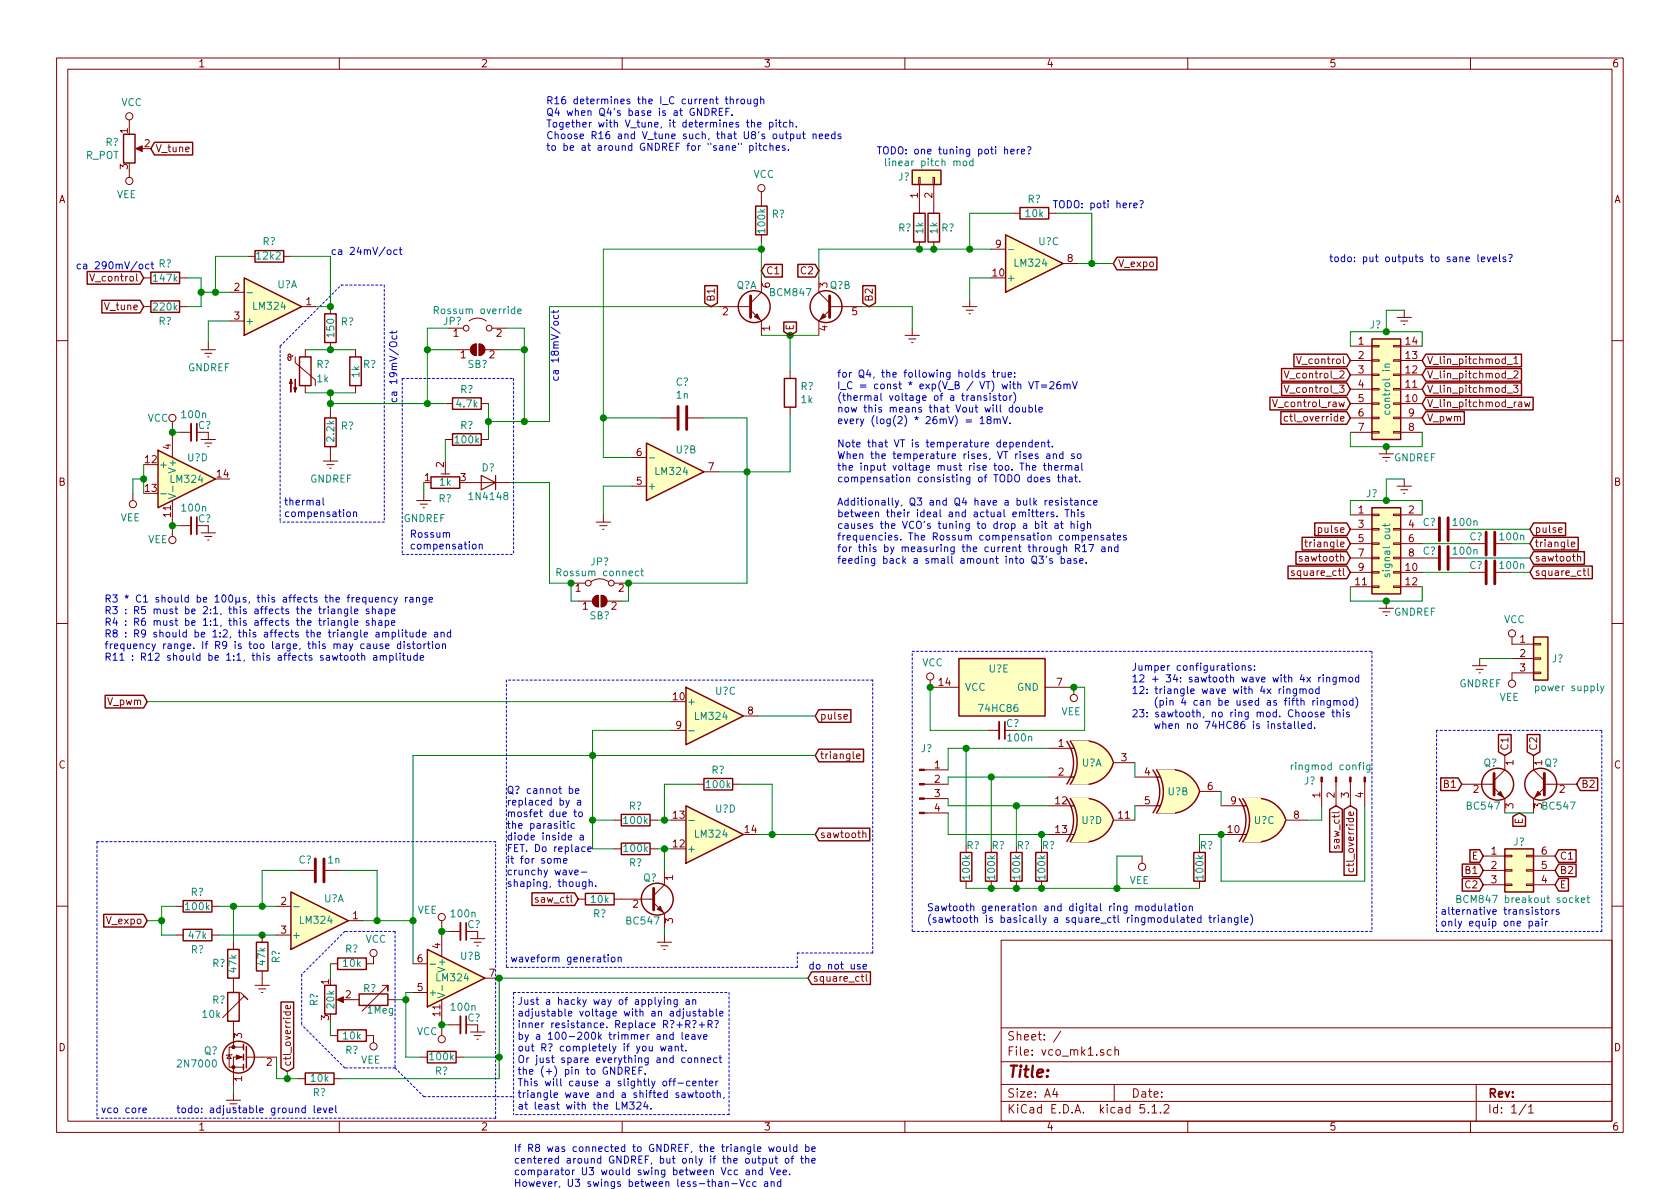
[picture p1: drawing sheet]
<svg xmlns="http://www.w3.org/2000/svg" width="297mm" height="210mm" viewBox="0 0 297 210" stroke-linecap="round" stroke-linejoin="round" font-family="sans-serif">
<defs><g id="words">
<text font-size="2.8" fill="#840000" x="178" y="190.5">Title:</text>
<g font-size="2.1" fill="#840000">
<text x="178" y="184">Sheet: /</text>
<text x="178" y="186.7">File: vco_mk1.sch</text>
<text x="178" y="196.9">KiCad E.D.A. kicad 5.1.2</text>
<text x="178" y="194.1">Size: A4</text>
<text x="200" y="194.1">Date:</text>
<text x="263" y="194.1">Rev:</text>
<text x="263" y="196.9">Id: 1/1</text>
</g>
<g font-size="1.8" fill="#840000">
<text x="35" y="11.9">1</text>
<text x="85" y="11.9">2</text>
<text x="135" y="11.9">3</text>
<text x="185" y="11.9">4</text>
<text x="235" y="11.9">5</text>
<text x="285" y="11.9">6</text>
<text x="22.6" y="23.6" transform="rotate(-90 22.6 23.6)">1</text>
<text x="22.6" y="29.9" transform="rotate(-90 22.6 29.9)">3</text>
<text x="25.6" y="26">2</text>
<text x="27.5" y="26.9">V_tune</text>
<text x="10.4" y="35.9">A</text>
<text x="162.3" y="35" transform="rotate(-90 162.3 35)">1</text>
<text x="164.8" y="35" transform="rotate(-90 164.8 35)">2</text>
<text x="285.4" y="35.9">A</text>
<text x="176" y="43.8">9</text>
<text x="188.7" y="46.3">8</text>
<text x="197.6" y="47.2">V_expo</text>
<text x="16.5" y="49.8">V_control</text>
<text x="41.4" y="51.4">2</text>
<text x="54.1" y="54">1</text>
<text x="126.4" y="53.4" transform="rotate(-90 126.4 53.4)">B1</text>
<text x="135.4" y="48.5">C1</text>
<text x="136.1" y="50.9" transform="rotate(-90 136.1 50.9)">6</text>
<text x="141.7" y="48.5">C2</text>
<text x="146.3" y="50.9" transform="rotate(-90 146.3 50.9)">3</text>
<text x="154.3" y="53.4" transform="rotate(-90 154.3 53.4)">B2</text>
<text x="175.6" y="48.9">10</text>
<text x="18.7" y="54.9">V_tune</text>
<text x="41.4" y="56.5">3</text>
<text x="80.2" y="59.6">1</text>
<text x="87.8" y="59.6">2</text>
<text x="127.8" y="55.7">2</text>
<text x="136.1" y="58.5" transform="rotate(-90 136.1 58.5)">1</text>
<text x="140.3" y="58.5" transform="rotate(-90 140.3 58.5)">E</text>
<text x="146.3" y="58.5" transform="rotate(-90 146.3 58.5)">4</text>
<text x="150.6" y="55.7">5</text>
<text x="81.4" y="63.4">1</text>
<text x="86.5" y="63.4">2</text>
<text x="229.8" y="64.4">V_control</text>
<text x="240.2" y="61">1</text>
<text x="240.2" y="63.5">2</text>
<text x="248.6" y="63.5">13</text>
<text x="248.6" y="61">14</text>
<text x="252.2" y="64.4">V_lin_pitchmod_1</text>
<text x="227.8" y="66.9">V_control_2</text>
<text x="227.8" y="69.5">V_control_3</text>
<text x="240.2" y="66">3</text>
<text x="240.2" y="68.6">4</text>
<text x="240.2" y="71.1">5</text>
<text x="248.6" y="71.1">10</text>
<text x="248.6" y="68.6">11</text>
<text x="248.6" y="66">12</text>
<text x="252.2" y="66.9">V_lin_pitchmod_2</text>
<text x="252.2" y="69.5">V_lin_pitchmod_3</text>
<text x="225.8" y="72">V_control_raw</text>
<text x="227.9" y="74.5">ctl_override</text>
<text x="240.2" y="73.7">6</text>
<text x="240.2" y="76.2">7</text>
<text x="249.1" y="76.2">8</text>
<text x="249.1" y="73.7">9</text>
<text x="252.2" y="72">V_lin_pitchmod_raw</text>
<text x="252.2" y="74.5">V_pwm</text>
<text x="25.7" y="81.9">12</text>
<text x="30.2" y="79.5" transform="rotate(-90 30.2 79.5)">4</text>
<text x="78.5" y="82.6" transform="rotate(-90 78.5 82.6)">2</text>
<text x="112.5" y="80.6">6</text>
<text x="125.2" y="83.2">7</text>
<text x="10.4" y="85.9">B</text>
<text x="25.7" y="87">13</text>
<text x="38.4" y="84.4">14</text>
<text x="75.1" y="85.1">1</text>
<text x="81.4" y="85.1">3</text>
<text x="112.5" y="85.7">5</text>
<text x="285.4" y="85.9">B</text>
<text x="30.2" y="91.4" transform="rotate(-90 30.2 91.4)">11</text>
<text x="233.3" y="94.2">pulse</text>
<text x="240.2" y="90.8">1</text>
<text x="240.2" y="93.3">3</text>
<text x="240.2" y="95.9">5</text>
<text x="249.1" y="90.8">2</text>
<text x="249.1" y="93.3">4</text>
<text x="249.1" y="95.9">6</text>
<text x="271.3" y="94.2">pulse</text>
<text x="229.1" y="101.8">square_ctl</text>
<text x="230.2" y="99.3">sawtooth</text>
<text x="231.6" y="96.8">triangle</text>
<text x="240.2" y="98.4">7</text>
<text x="240.2" y="101">9</text>
<text x="248.6" y="101">10</text>
<text x="249.1" y="98.4">8</text>
<text x="271.3" y="96.8">triangle</text>
<text x="271.3" y="99.3">sawtooth</text>
<text x="271.3" y="101.8">square_ctl</text>
<text x="101.8" y="104.6">1</text>
<text x="103" y="107.8">1</text>
<text x="108.1" y="107.8">2</text>
<text x="109.4" y="104.6">2</text>
<text x="239.7" y="103.5">11</text>
<text x="248.6" y="103.5">12</text>
<text x="268.8" y="113.7">1</text>
<text x="268.8" y="116.2">2</text>
<text x="268.8" y="118.7">3</text>
<text x="19" y="124.7">V_pwm</text>
<text x="119" y="123.8">10</text>
<text x="166" y="121.3">14</text>
<text x="186.8" y="121.3">7</text>
<text x="119.5" y="128.9">9</text>
<text x="132.2" y="126.4">8</text>
<text x="144.9" y="127.2">pulse</text>
<text x="10.4" y="135.9">C</text>
<text x="144.9" y="134.2">triangle</text>
<text x="165.3" y="135.9">1</text>
<text x="187.1" y="132.1">1</text>
<text x="187.1" y="137.2">2</text>
<text x="198.3" y="134.6">3</text>
<text x="202.4" y="137.2">4</text>
<text x="266.7" y="132.8" transform="rotate(-90 266.7 132.8)">C1</text>
<text x="267.6" y="135.4" transform="rotate(-90 267.6 135.4)">1</text>
<text x="271.8" y="132.8" transform="rotate(-90 271.8 132.8)">C2</text>
<text x="272.7" y="135.4" transform="rotate(-90 272.7 135.4)">1</text>
<text x="285.4" y="135.9">C</text>
<text x="165.3" y="138.4">2</text>
<text x="165.3" y="141">3</text>
<text x="165.3" y="143.5">4</text>
<text x="186.7" y="142.2">12</text>
<text x="202.4" y="142.2">5</text>
<text x="213.5" y="139.7">6</text>
<text x="217.6" y="142.2">9</text>
<text x="233.4" y="141.1" transform="rotate(-90 233.4 141.1)">1</text>
<text x="236" y="141.1" transform="rotate(-90 236 141.1)">2</text>
<text x="238.5" y="141.1" transform="rotate(-90 238.5 141.1)">3</text>
<text x="241" y="141.1" transform="rotate(-90 241 141.1)">4</text>
<text x="255.4" y="139.3">B1</text>
<text x="260.5" y="140.2">2</text>
<text x="267.6" y="143" transform="rotate(-90 267.6 143)">3</text>
<text x="272.7" y="143" transform="rotate(-90 272.7 143)">3</text>
<text x="275.7" y="140.2">2</text>
<text x="279.6" y="139.3">B2</text>
<text x="119" y="149.9">12</text>
<text x="119" y="144.8">13</text>
<text x="131.7" y="147.3">14</text>
<text x="144.9" y="148.2">sawtooth</text>
<text x="186.7" y="147.3">13</text>
<text x="197.8" y="144.8">11</text>
<text x="217.1" y="147.3">10</text>
<text x="228.8" y="144.8">8</text>
<text x="236.9" y="149.7" transform="rotate(-90 236.9 149.7)">saw_ctl</text>
<text x="269.2" y="145.7" transform="rotate(-90 269.2 145.7)">E</text>
<text x="119" y="155.7" transform="rotate(-90 119 155.7)">1</text>
<text x="239.4" y="153.3" transform="rotate(-90 239.4 153.3)">ctl_override</text>
<text x="259.2" y="154.6">B1</text>
<text x="260.3" y="152">E</text>
<text x="263.7" y="151.1">1</text>
<text x="263.7" y="153.7">2</text>
<text x="272.6" y="153.7">5</text>
<text x="272.6" y="151.1">6</text>
<text x="275.7" y="152">C1</text>
<text x="275.7" y="154.6">B2</text>
<text x="49.7" y="160">2</text>
<text x="95" y="159.6">saw_ctl</text>
<text x="111.9" y="160.5">2</text>
<text x="259.2" y="157.1">C2</text>
<text x="263.7" y="156.2">3</text>
<text x="272.6" y="156.2">4</text>
<text x="275.7" y="157.1">E</text>
<text x="18.9" y="163.4">V_expo</text>
<text x="49.7" y="165.1">3</text>
<text x="62.4" y="162.6">1</text>
<text x="77.9" y="167.7" transform="rotate(-90 77.9 167.7)">4</text>
<text x="119" y="163.3" transform="rotate(-90 119 163.3)">3</text>
<text x="73.8" y="170.2">6</text>
<text x="86.5" y="172.7">7</text>
<text x="143.7" y="173.6">square_ctl</text>
<text x="58.2" y="174.1" transform="rotate(-90 58.2 174.1)">1</text>
<text x="61.1" y="176.5">2</text>
<text x="73.8" y="175.3">5</text>
<text x="77.9" y="179.6" transform="rotate(-90 77.9 179.6)">11</text>
<text x="10.4" y="185.9">D</text>
<text x="42.8" y="183.6" transform="rotate(-90 42.8 183.6)">3</text>
<text x="58.2" y="180.4" transform="rotate(-90 58.2 180.4)">3</text>
<text x="285.4" y="185.9">D</text>
<text x="42.8" y="191.2" transform="rotate(-90 42.8 191.2)">1</text>
<text x="47.1" y="188.5">2</text>
<text x="51.4" y="188.7" transform="rotate(-90 51.4 188.7)">ctl_override</text>
<text x="35" y="199.9">1</text>
<text x="85" y="199.9">2</text>
<text x="135" y="199.9">3</text>
<text x="185" y="199.9">4</text>
<text x="235" y="199.9">5</text>
<text x="285" y="199.9">6</text>
</g>
<g font-size="1.8" fill="#008484">
<text x="21.4" y="18.8">VCC</text>
<text x="15.2" y="28.1">R_POT</text>
<text x="18.7" y="25.8">R?</text>
<text x="157.5" y="29.4">linear pitch mod</text>
<text x="20.6" y="35">VEE</text>
<text x="133.2" y="31.5">VCC</text>
<text x="158.8" y="31.9">J?</text>
<text x="181.7" y="35.9">R?</text>
<text x="135.3" y="41.1" transform="rotate(-90 135.3 41.1)">100k</text>
<text x="136.5" y="38.5">R?</text>
<text x="158.8" y="40.9">R?</text>
<text x="163.2" y="41.3" transform="rotate(-90 163.2 41.3)">1k</text>
<text x="165.8" y="41.3" transform="rotate(-90 165.8 41.3)">1k</text>
<text x="166.4" y="40.9">R?</text>
<text x="181.4" y="38.4">10k</text>
<text x="28" y="47.3">R?</text>
<text x="45.5" y="45.9">12k2</text>
<text x="46.4" y="43.4">R?</text>
<text x="179.5" y="47.2">LM324</text>
<text x="183.6" y="43.4">U?C</text>
<text x="27.3" y="49.8">147k</text>
<text x="49" y="51">U?A</text>
<text x="130.1" y="51.1">Q?A</text>
<text x="136.3" y="52.4">BCM847</text>
<text x="146.7" y="51.1">Q?B</text>
<text x="177.9" y="49.8">+</text>
<text x="27.3" y="54.9">220k</text>
<text x="28" y="57.4">R?</text>
<text x="43.3" y="57.4">+</text>
<text x="44.9" y="54.8">LM324</text>
<text x="59.1" y="59.5" transform="rotate(-90 59.1 59.5)">150</text>
<text x="60.3" y="57.6">R?</text>
<text x="77.2" y="55.5">Rossum override</text>
<text x="78.4" y="57.4">JP?</text>
<text x="242.2" y="58.1">J?</text>
<text x="33.2" y="65.7">GNDREF</text>
<text x="56" y="65.1">R?</text>
<text x="64.2" y="65.1">R?</text>
<text x="82.7" y="65.1">SB?</text>
<text x="56.1" y="67.6">1k</text>
<text x="63.6" y="66.7" transform="rotate(-90 63.6 66.7)">1k</text>
<text x="81.4" y="69.5">R?</text>
<text x="119.5" y="68.2">C?</text>
<text x="119.6" y="70.5">1n</text>
<text x="141.6" y="69">R?</text>
<text x="141.7" y="71.3">1k</text>
<text x="26.1" y="74.6">VCC</text>
<text x="32.3" y="74">100n</text>
<text x="35" y="75.9">C?</text>
<text x="59.1" y="78" transform="rotate(-90 59.1 78)">2.2k</text>
<text x="60.3" y="76">R?</text>
<text x="80.8" y="72.1">4.7k</text>
<text x="81.4" y="75.9">R?</text>
<text x="245.8" y="72.8" transform="rotate(-90 245.8 72.8)">control in</text>
<text x="28.1" y="82.8">+</text>
<text x="31.1" y="83.2" transform="rotate(-90 31.1 83.2)">V+</text>
<text x="33.1" y="81.6">U?D</text>
<text x="80.6" y="78.4">100k</text>
<text x="85.2" y="83.4">D?</text>
<text x="116" y="84">LM324</text>
<text x="119.5" y="80.2">U?B</text>
<text x="246.5" y="81.6">GNDREF</text>
<text x="30.3" y="85.4">LM324</text>
<text x="54.8" y="85.3">GNDREF</text>
<text x="77.5" y="88.8">R?</text>
<text x="77.8" y="85.9">1k</text>
<text x="83.3" y="88.4">1N4148</text>
<text x="114.4" y="86.6">+</text>
<text x="241.6" y="87.9">J?</text>
<text x="21.3" y="92.2">VEE</text>
<text x="32.3" y="90.5">100n</text>
<text x="35" y="92.4">C?</text>
<text x="71.3" y="92.3">GNDREF</text>
<text x="251.6" y="93">C?</text>
<text x="257.1" y="93">100n</text>
<text x="259.8" y="95.5">C?</text>
<text x="265.3" y="95.5">100n</text>
<text x="26.2" y="96.1">VEE</text>
<text x="98.9" y="101.9">Rossum connect</text>
<text x="104.4" y="100">JP?</text>
<text x="245.8" y="101.5" transform="rotate(-90 245.8 101.5)">signal out</text>
<text x="251.6" y="98.1">C?</text>
<text x="257.1" y="98.1">100n</text>
<text x="259.8" y="100.6">C?</text>
<text x="265.3" y="100.6">100n</text>
<text x="104.3" y="109.5">SB?</text>
<text x="246.5" y="108.9">GNDREF</text>
<text x="265.9" y="110.2">VCC</text>
<text x="163" y="117.8">VCC</text>
<text x="174.8" y="118.9">U?E</text>
<text x="274.4" y="117.1">J?</text>
<text x="121.4" y="124.7">+</text>
<text x="126.5" y="122.9">U?C</text>
<text x="170.6" y="122.2">VCC</text>
<text x="173.3" y="125.9">74HC86</text>
<text x="179.8" y="122.2">GND</text>
<text x="258" y="121.5">GNDREF</text>
<text x="265.1" y="123.9">VEE</text>
<text x="271.8" y="122.2">power supply</text>
<text x="123" y="127.3">LM324</text>
<text x="177.9" y="128.6">C?</text>
<text x="178.3" y="131.1">100n</text>
<text x="187.6" y="126.5">VEE</text>
<text x="125.8" y="136.8">R?</text>
<text x="162.8" y="133">J?</text>
<text x="191.2" y="135.6">U?A</text>
<text x="228.9" y="136.2">ringmod config</text>
<text x="262.3" y="135.6">Q?</text>
<text x="273.1" y="135.6">Q?</text>
<text x="111.2" y="143.2">R?</text>
<text x="125" y="139.4">100k</text>
<text x="126.5" y="143.7">U?D</text>
<text x="206.5" y="140.6">U?B</text>
<text x="230.6" y="138.7">J?</text>
<text x="259.5" y="143.2">BC547</text>
<text x="272.8" y="143.2">BC547</text>
<text x="110.4" y="145.7">100k</text>
<text x="123" y="148.1">LM324</text>
<text x="191.2" y="145.7">U?D</text>
<text x="221.7" y="145.7">U?C</text>
<text x="267.6" y="149.5">J?</text>
<text x="52.8" y="152.7">C?</text>
<text x="58" y="152.7">1n</text>
<text x="110.4" y="150.7">100k</text>
<text x="111.2" y="153.2">R?</text>
<text x="113.7" y="155.9">Q?</text>
<text x="121.4" y="150.7">+</text>
<text x="170.9" y="150.2">R?</text>
<text x="171.5" y="155.4" transform="rotate(-90 171.5 155.4)">100k</text>
<text x="175.3" y="150.2">R?</text>
<text x="175.9" y="155.4" transform="rotate(-90 175.9 155.4)">100k</text>
<text x="179.8" y="150.2">R?</text>
<text x="180.4" y="155.4" transform="rotate(-90 180.4 155.4)">100k</text>
<text x="184.2" y="150.2">R?</text>
<text x="184.8" y="155.4" transform="rotate(-90 184.8 155.4)">100k</text>
<text x="212.2" y="150.2">R?</text>
<text x="212.8" y="155.4" transform="rotate(-90 212.8 155.4)">100k</text>
<text x="32.9" y="161">100k</text>
<text x="33.7" y="158.4">R?</text>
<text x="57.3" y="159.6">U?A</text>
<text x="73.8" y="161.6">VEE</text>
<text x="104.6" y="159.7">10k</text>
<text x="199.7" y="156.3">VEE</text>
<text x="258.7" y="159.7">BCM847 breakout socket</text>
<text x="33.5" y="166">47k</text>
<text x="51.6" y="166">+</text>
<text x="53.1" y="163.4">LM324</text>
<text x="64.6" y="166.7">VCC</text>
<text x="79.9" y="162.2">100n</text>
<text x="82.7" y="164.1">C?</text>
<text x="104.9" y="162.2">R?</text>
<text x="110.9" y="163.5">BC547</text>
<text x="33.8" y="168.6">R?</text>
<text x="37.5" y="171">R?</text>
<text x="41.8" y="171.9" transform="rotate(-90 41.8 171.9)">47k</text>
<text x="46.9" y="170.6" transform="rotate(-90 46.9 170.6)">47k</text>
<text x="49.5" y="170.3" transform="rotate(-90 49.5 170.3)">R?</text>
<text x="60.8" y="171">10k</text>
<text x="61" y="168.4">R?</text>
<text x="77.3" y="173.5">LM324</text>
<text x="78.7" y="171.5" transform="rotate(-90 78.7 171.5)">V+</text>
<text x="81.4" y="169.7">U?B</text>
<text x="37.5" y="177.5">R?</text>
<text x="56.2" y="177.9" transform="rotate(-90 56.2 177.9)">R?</text>
<text x="59.1" y="178.3" transform="rotate(-90 59.1 178.3)">20k</text>
<text x="64.2" y="175.4">R?</text>
<text x="65" y="179.2">1Meg</text>
<text x="75.7" y="176.1">+</text>
<text x="79.9" y="178.7">100n</text>
<text x="35.9" y="180">10k</text>
<text x="60.8" y="183.8">10k</text>
<text x="73.7" y="183.1">VCC</text>
<text x="82.7" y="180.6">C?</text>
<text x="31.7" y="188.8">2N7000</text>
<text x="36.1" y="186.5">Q?</text>
<text x="55" y="191.3">10k</text>
<text x="61.1" y="186.4">R?</text>
<text x="63.8" y="188.1">VEE</text>
<text x="76.1" y="187.5">100k</text>
<text x="76.9" y="190">R?</text>
<text x="55.3" y="193.8">R?</text>
</g>
<g font-size="1.8" fill="#0000c2">
<text x="96.5" y="18.4">R16 determines the I_C current through</text>
<text x="96.5" y="20.5">Q4 when Q4's base is at GNDREF.</text>
<text x="96.5" y="22.5">Together with V_tune, it determines the pitch.</text>
<text x="96.5" y="24.6">Choose R16 and V_tune such, that U8's output needs</text>
<text x="96.5" y="26.7">to be at around GNDREF for &quot;sane&quot; pitches.</text>
<text x="154.9" y="27.3">TODO: one tuning poti here?</text>
<text x="186.1" y="36.8">TODO: poti here?</text>
<text x="13.3" y="47.6">ca 290mV/oct</text>
<text x="58.4" y="45.1">ca 24mV/oct</text>
<text x="234.9" y="46.3">todo: put outputs to sane levels?</text>
<text x="70.2" y="71.4" transform="rotate(-90 70.2 71.4)">ca 19mV/Oct</text>
<text x="98.8" y="67.6" transform="rotate(-90 98.8 67.6)">ca 18mV/oct</text>
<text x="148" y="66.8">for Q4, the following holds true:</text>
<text x="148" y="68.8">I_C = const * exp(V_B / VT) with VT=26mV</text>
<text x="148" y="70.9">(thermal voltage of a transistor)</text>
<text x="148" y="72.9">now this means that Vout will double</text>
<text x="148" y="75">every (log(2) * 26mV) = 18mV.</text>
<text x="148" y="79.1">Note that VT is temperature dependent.</text>
<text x="148" y="81.2">When the temperature rises, VT rises and so</text>
<text x="148" y="83.2">the input voltage must rise too. The thermal</text>
<text x="50.2" y="89.4">thermal</text>
<text x="148" y="85.3">compensation consisting of TODO does that.</text>
<text x="148" y="89.4">Additionally, Q3 and Q4 have a bulk resistance</text>
<text x="50.2" y="91.4">compensation</text>
<text x="72.4" y="95.1">Rossum</text>
<text x="148" y="91.5">between their ideal and actual emitters. This</text>
<text x="148" y="93.5">causes the VCO's tuning to drop a bit at high</text>
<text x="148" y="95.6">frequencies. The Rossum compensation compensates</text>
<text x="72.4" y="97.1">compensation</text>
<text x="148" y="97.6">for this by measuring the current through R17 and</text>
<text x="148" y="99.7">feeding back a small amount into Q3's base.</text>
<text x="18.4" y="106.5">R3 * C1 should be 100µs, this affects the frequency range</text>
<text x="18.4" y="108.6">R3 : R5 must be 2:1, this affects the triangle shape</text>
<text x="18.4" y="110.7">R4 : R6 must be 1:1, this affects the triangle shape</text>
<text x="18.4" y="112.7">R8 : R9 should be 1:2, this affects the triangle amplitude and</text>
<text x="18.4" y="114.8">frequency range. If R9 is too large, this may cause distortion</text>
<text x="18.4" y="116.8">R11 : R12 should be 1:1, this affects sawtooth amplitude</text>
<text x="200" y="118.6">Jumper configurations:</text>
<text x="200" y="120.7">12 + 34: sawtooth wave with 4x ringmod</text>
<text x="200" y="122.7">12: triangle wave with 4x ringmod</text>
<text x="202" y="124.8">(pin 4 can be used as fifth ringmod)</text>
<text x="200" y="126.8">23: sawtooth, no ring mod. Choose this</text>
<text x="202" y="128.9">when no 74HC86 is installed.</text>
<text x="89.5" y="140.4">Q? cannot be</text>
<text x="89.5" y="142.4">replaced by a</text>
<text x="89.5" y="144.5">mosfet due to</text>
<text x="89.5" y="146.6">the parasitic</text>
<text x="89.5" y="148.6">diode inside a</text>
<text x="89.5" y="150.7">FET. Do replace</text>
<text x="89.5" y="152.7">it for some</text>
<text x="89.5" y="154.8">crunchy wave-</text>
<text x="89.5" y="156.8">shaping, though.</text>
<text x="163.8" y="161.1">Sawtooth generation and digital ring modulation</text>
<text x="254.6" y="161.8">alternative transistors</text>
<text x="163.8" y="163.2">(sawtooth is basically a square_ctl ringmodulated triangle)</text>
<text x="254.6" y="163.8">only equip one pair</text>
<text x="90.2" y="170.2">waveform generation</text>
<text x="142.9" y="171.4">do not use</text>
<text x="91.4" y="177.7">Just a hacky way of applying an</text>
<text x="91.4" y="179.8">adjustable voltage with an adjustable</text>
<text x="91.4" y="181.8">inner resistance. Replace R?+R?+R?</text>
<text x="91.4" y="183.9">by a 100-200k trimmer and leave</text>
<text x="91.4" y="185.9">out R? completely if you want.</text>
<text x="91.4" y="188">Or just spare everything and connect</text>
<text x="91.4" y="190">the (+) pin to GNDREF.</text>
<text x="17.8" y="196.8">vco core</text>
<text x="31.1" y="196.8">todo: adjustable ground level</text>
<text x="91.4" y="192.1">This will cause a slightly off-center</text>
<text x="91.4" y="194.2">triangle wave and a shifted sawtooth,</text>
<text x="91.4" y="196.2">at least with the LM324.</text>
<text x="90.8" y="203.7">If R8 was connected to GNDREF, the triangle would be</text>
<text x="90.8" y="205.8">centered around GNDREF, but only if the output of the</text>
<text x="90.8" y="207.8">comparator U3 would swing between Vcc and Vee.</text>
<text x="90.8" y="209.9">However, U3 swings between less-than-Vcc and</text>
</g>
</g></defs>
<g fill="none" stroke="#840000" stroke-width=".18">
<path d="M10 10.3h277v189.9h-277zM12 12.2h273v186.1h-273zM60 10.3v1.9M110 10.3v1.9M160 10.3v1.9M210 10.3v1.9M260 10.3v1.9M22.9 21.2v1.3M22.9 30.1v1.3M24.4 26.3h1M134.6 33.9v2.5M162.4 31.4h.3v1.2h-.3z"/>
<path d="M162.6 32.6v5.1M165 31.4h.2v1.2h-.2zM165.1 32.6v5.1M179.1 37.7h1.2M185.4 37.7h1.3M15.9 48.4l.4 1.3 .4-1.3M25.4 49.1h1.3M25.4 54.2h1.3M31.7 49.1h1.3M31.7 54.2h1.3M40.6 51.7h2.6M40.6 56.8h2.6"/>
<path d="M43.8 45.3h1.3M50.2 45.3h1.2M53.3 54.2h2.6M58.4 54.2v1.3M82.9 56.8a2.53 2.53 0 0 1 3.1 0M87 58h2.5M127 54.2h5.7M132.7 54.9l1.9 1.9v2.5M134.6 41.5v1.3M134.6 49.1v2.6l-1.9 1.9M144.8 49.1v2.6l1.9 1.9M146.7 54.9l-1.9 1.9v2.5"/>
<path d="M146.7 54.2h5.7M160 59.3h2.6M160.7 59.9h1.2M161.3 58v1.3M162.6 42.8v1.3M165.1 42.8v1.3M170.2 54.2h2.5M170.8 54.9h1.3M171.3 55.5h.3M171.4 53v1.2M175.3 44.1h2.5M188 46.6h2.5"/>
<path d="M247 56.1h2.6M247.6 56.8h1.3M248.2 57.4h.2M248.3 54.9v1.2M10 60.2h2M30.5 74.5v1.3M30.5 77.1v3.8M31.7 76.4h2.1M35.6 77.7h2.5M35.6 61.8h2.5M36.2 62.5h1.3M36.2 78.4h1.3"/>
<path d="M36.7 63.1h.3M36.7 79h.3M36.8 60.6v1.2M36.8 76.4v1.3M51.8 62.9l-.2 .2h-.4l-.2-.1v-.3l.3-.1 .1 .2v.8l-.1 .1-.3-.1v-.2l-.2-.2M52.2 63.1v1l3.6 3.1v1M54 61.8v1.3M54 68.2v1.3M58.4 60.6v1.2M58.4 72.6v1.3M58.4 79v2.5M62.9 61.8v1.3"/>
<path d="M62.9 68.2v1.3M78.7 77.7h1.3M78.7 71.4h1.3M80.6 61.8h2.6M83.4 61.2l.4-.3 .4-.1v2.1a1.03 1.03 0 0 1-.9-.6 1.03 1.03 0 0 1 .1-1.1zM84.7 60.8a1.02 1.02 0 0 1 1 1 1.02 1.02 0 0 1-1 1.1zM85.1 77.7h1.3M85.1 71.4h1.3M85.7 61.8h2.6M116.8 73.9h2.8M121.7 73.9h2.8M139.7 65.7v1.2"/>
<path d="M139.7 72v1.3M161.2 60.6h.2M225 70.7l.4 1.2 .5-1.2M227.1 65.6l.4 1.2 .4-1.2M227.1 68.1l.4 1.3 .4-1.3M227.7 73.7l-.4-.1-.2 .3 .1 .5h.5M229.2 63l.5 1.3 .4-1.3M236.7 71.1l.3 .8 .2-.6 .3 .6 .2-.8M237 74l.6-.1v-.2l-.4-.1-.2 .2 .1 .6h.5M238.8 71.4h3.8M238.8 73.9h3.8M238.8 61.2h3.8"/>
<path d="M238.8 68.8h3.8M238.8 66.3h3.8M238.8 63.7h3.8M238.8 76.4h3.8M242.6 76.3h1.2v.3h-1.2zM242.6 73.8h1.2v.2h-1.2zM242.6 71.2h1.2v.3h-1.2zM242.6 68.7h1.2v.3h-1.2zM242.6 66.2h1.2v.2h-1.2zM242.6 63.6h1.2v.3h-1.2zM242.6 61.1h1.2v.2h-1.2zM245.1 79v1.3"/>
<path d="M246.4 76.3h1.2v.3h-1.2zM246.4 73.8h1.2v.2h-1.2zM246.4 71.2h1.2v.3h-1.2zM246.4 68.7h1.2v.3h-1.2zM246.4 66.2h1.2v.2h-1.2zM246.4 63.6h1.2v.3h-1.2zM246.4 61.1h1.2v.2h-1.2zM247.6 71.4h3.9M247.6 73.9h3.9M247.6 61.2h3.9M247.6 68.8h3.9M247.6 66.3h3.9"/>
<path d="M247.6 63.7h3.9M247.6 76.4h3.9M266.5 64.4h.9M266.5 67h.9M266.5 69.5h.9M267.6 68.1h.8l-.4 .5 .3 .1 .1 .5-.3 .2-.5-.1M267.7 63.4l.3-.4v1.3M267.7 65.7l.4-.1 .3 .3-.8 .9h.8M267.7 64.3h.7M268.5 71.1h.5l.1 .8M269.1 71.4h-.5l-.1 .2 .1 .3h.5M269.5 71.1l.3 .8 .2-.6 .3 .6 .2-.8"/>
<path d="M285 60.2h2M23.5 87.2v1.3M30.5 88.5v3.8M30.5 93.6v1.3M31.7 93h2.1M35.6 94.2h2.5M36.2 94.9h1.3M36.7 95.5h.3M36.8 93v1.2M57.1 81.5h2.6M57.8 82.2h1.3M58.3 82.8h.2"/>
<path d="M73.7 88.5h2.5M74.3 89.1h1.3M74.8 89.8h.3M74.9 87.2v1.3M78 83.8h1.5M78.7 82.8v1M82.5 85.3h7.7M105.4 92.3h2.5M106 93h1.3M106.6 93.6h.2M106.7 91.1v1.2M111.8 86h2.5"/>
<path d="M111.8 80.9h2.5M124.5 83.4h2.5M230.7 95.9h.5M230.9 95.4v1.1l.3 .2M238.8 93.6h3.8M238.8 91.1h3.8M238.8 96.1h3.8M238.8 98.7h3.8M242.6 98.5h1.2v.3h-1.2zM242.6 96h1.2v.3h-1.2zM242.6 93.5h1.2v.2h-1.2zM242.6 90.9h1.2v.3h-1.2z"/>
<path d="M243.8 80.3h2.6M244.5 80.9h1.2M245 81.5h.2M246.4 98.5h1.2v.3h-1.2zM246.4 96h1.2v.3h-1.2zM246.4 93.5h1.2v.2h-1.2zM246.4 90.9h1.2v.3h-1.2zM247 86h2.6M247.6 93.6h3.9M247.6 91.1h3.9M247.6 96.1h3.9M247.6 98.7h3.9"/>
<path d="M247.6 86.6h1.3M248.2 87.2h.2M248.3 84.7v1.3M256.3 93.6h2.8M256.3 98.7h2.8M264.5 96.1h2.8M275.6 93.7l.6-.1-.1-.2-.3-.1-.2 .2 .1 .6h.4M277.8 96.3l.6-.1v-.3h-.4l-.2 .1 .1 .6h.5M278.9 98.5l.2-.1h.3l.1 .8M278.9 98v1.2M10 110.3h2M101 103.1h2.5"/>
<path d="M102.2 106.3h2.6M104.5 102.9a2.53 2.53 0 0 1 3.1 0M105 105.6l.4-.3h.4v2a1.03 1.03 0 0 1-.9-.6 1.03 1.03 0 0 1 .1-1.1zM106.3 105.3a1.02 1.02 0 0 1 1 1 1.02 1.02 0 0 1-1 1zM107.3 106.3h2.6M108.6 103.1h2.5M228.8 101l-.3-.1-.2 .2 .1 .2 .4 .1v.3h-.5M238.8 101.2h3.8M238.8 103.8h3.8M242.6 103.6h1.2v.3h-1.2zM242.6 101.1h1.2v.2h-1.2zM243.8 107.6h2.6"/>
<path d="M244.5 108.2h1.2M245 108.8h.2M245.1 106.3v1.3M246.4 103.6h1.2v.3h-1.2zM246.4 101.1h1.2v.2h-1.2zM247.6 101.2h3.9M247.6 103.8h3.9M260.3 117.7h2.6M261 118.4h1.3M261.5 119h.2M261.6 116.5v1.2M264.5 101.2h2.8"/>
<path d="M267.3 112.6v1.3h3.8M267.3 116.5h3.8M271.1 118.9h1.3v.2h-1.3zM271.1 116.3h1.3v.3h-1.3zM271.1 113.8h1.3v.2h-1.3zM271.1 119h-3.8v1.3M279.9 100.9h.5M280.1 100.5v1.1l.3 .2M280.8 100.5v1.1l.2 .2M285 110.3h2M118.7 129.2h2.6M123.2 138.7h1.3"/>
<path d="M129.5 138.7h1.3M131.4 126.6h2.6M149.2 126.7l.6-.1v-.2l-.4-.1-.2 .2 .1 .6h.5M151.5 133.7l.6-.1-.1-.2-.4-.1-.1 .2v.6h.5M163.4 138.7h4.2M163.4 136.1h4.2M164.5 120.3v1.2h5M174.6 129.2h2.1M184.8 121.5h5.1v1.3M185.4 137.4h4.5M185.4 132.3h4.5M196.8 134.9h3.9"/>
<path d="M200.7 137.4h4.4M212.1 139.9h3.8M233.7 138.3v4.2M236.2 138.3v4.2M238.8 138.3v4.2M241.3 138.3v4.2M258.4 138.7h5.8M264.2 139.3l1.9 1.9v2.6M266.1 133.6v2.5l-1.9 1.9M271.1 133.6v2.5l1.9 1.9M273 139.3l-1.9 1.9v2.6M273 138.7h5.8"/>
<path d="M52.7 153.9h2.8M57.5 153.9h2.8M102.2 159h1.3M108.6 150.1h1.3M108.6 145h1.3M108.6 159h7M114.9 150.1h1.3M114.9 145h1.3M115.6 159.6l1.9 1.9v2.6M117.5 153.9v2.6l-1.9 1.9M152.6 147.4l.1-.1h.3l.1 .8M152.6 146.9v1.2"/>
<path d="M163.4 143.8h4.2M163.4 141.2h4.2M170.8 155.8v1.3M175.3 155.8v1.3M179.7 155.8v1.3M184.1 155.8v1.3M185.4 142.5h4.5M185.4 147.6h4.5M196.8 145h3.9M200.7 142.5h4.4M201.9 151.4v1.2M212.1 155.8v1.3"/>
<path d="M215.9 142.5h4.4M215.9 147.6h4.4M227.3 145h3.8M238.5 153.6v.3l.2 .3 .6-.2v-.4M239.3 143.6v.4l-.2 .2-.6-.1v-.5h.3l.1 .6M262.3 153.9h3.8M262.3 151.4h3.8M262.3 156.5h3.8M266.1 156.3h1.2v.3h-1.2zM266.1 153.8h1.2v.2h-1.2zM266.1 151.3h1.2v.2h-1.2zM269.9 156.3h1.2v.3h-1.2z"/>
<path d="M269.9 153.8h1.2v.2h-1.2zM269.9 151.3h1.2v.2h-1.2zM271.1 153.9h3.9M271.1 151.4h3.9M271.1 156.5h3.9M10 160.2h2M31.1 165.3h1.3M31.1 160.3h1.3M37.5 165.3h1.2M37.5 160.3h1.2M41.3 166.6v1.3M41.3 173v2.5"/>
<path d="M42.5 175.5l1.3 1.3-.6-.7-3.8 3.9M45.1 174.2h2.5M45.7 174.9h1.3M46.2 175.5h.3M46.4 165.3v1.3M46.4 171.7v2.5M48.9 165.3h2.5M48.9 160.3h2.5M50.1 178.9h1.3M50.6 178.9l-.1 .4 .2 .2 .6-.1v-.5M51.3 177.8l.1 .4-.2 .2-.6-.1v-.5h.2l.1 .6M58.4 170.4h1.3"/>
<path d="M59.9 176.8h1.1M61.6 162.8h2.5M62.2 176.8h1.3M66 169.2v1.2h-1.2M67.6 174.2h1v1.1v-1.1l-4.6 4.6M68.6 176.8h1.2M73 175.5h2.6M73 170.4h2.6M78.1 162.8v1.3M78.1 165.3v3.9M78.1 176.8v3.8M79.4 164.7h2"/>
<path d="M83.2 166h2.5M83.8 166.6h1.3M84.3 167.3h.3M84.5 164.7v1.3M85.7 173h2.6M116.2 166.6h2.5M116.8 167.3h1.3M117.3 167.9h.3M117.5 165.3v1.3M152.2 172.7h.5M152.4 172.3v1l.3 .2M153.2 172.3v1l.1 .2"/>
<path d="M177 166.3h108v32h-108zM285 160.2h2M40 194.6h2.5M40.5 186.6l.4 .6h-.8zM41 186.4l-.1 .2h-.8l-.1 .1M41.3 185.2h-.8v3.5h2.6M41.3 180.6v4.6M41.3 193.3v1.3M41.3 185.2h1.8M43.1 186.9h-1.8v5.1M43.6 186.9h5.3M52.7 190.7h1.3"/>
<path d="M58.4 183.1h1.3M59.1 190.7h1.2M60 198.3v1.9M64.8 183.1h1.2v1.3M74.3 186.9h1.3M78.1 181.9v1.2M79.4 181.2h2M80.6 186.9h1.3M83.2 182.5h2.5M83.8 183.1h1.3M84.3 183.8h.3M84.5 181.2v1.3"/>
<path d="M110 198.3v1.9M160 198.3v1.9M177 194.8h108M177 191.8h108M177 187.8h108M177 181.8h108M186.5 192.5l-.4 1h1M186.8 193v1M187.6 182.3l-1.3 2M196.5 185.7l-.4-.1-.3 .3v.6l.3 .1 .4-.1M197 191.8v3M197.1 185.7l.2-.1 .4 .1 .1 .9"/>
<path d="M197.1 185.1v1.5M202.3 195.3h-.7l-.1 .7 .3-.1 .5 .1 .1 .2-.1 .5-.2 .1-.6-.1M203 196.7v.1M203.7 195.8l.4-.5v1.5M203.7 196.8h.8M205.2 196.7v.1M205.8 195.5l.2-.2h.4l.3 .5-.9 1h.9M210 198.3v1.9M260 198.3v1.9M261 191.8v6.5M269.8 195.2l-1.2 2M270.3 195.8l.4-.5v1.5"/>
<path d="M270.3 196.8h.8"/>
<circle cx="22.9" cy="32" r=".63"/>
<circle cx="22.9" cy="20.6" r=".63"/>
<circle cx="134.6" cy="33.3" r=".63"/>
<circle cx="82.4" cy="58" r=".51"/>
<circle cx="86.5" cy="58" r=".51"/>
<circle cx="30.5" cy="73.9" r=".63"/>
<circle cx="23.5" cy="89.1" r=".63"/>
<circle cx="30.5" cy="95.5" r=".63"/>
<circle cx="104" cy="103.1" r=".51"/>
<circle cx="108.1" cy="103.1" r=".51"/>
<circle cx="164.5" cy="119.6" r=".63"/>
<circle cx="267.3" cy="112" r=".63"/>
<circle cx="189.9" cy="123.4" r=".63"/>
<circle cx="267.3" cy="120.9" r=".63"/>
<circle cx="201.9" cy="153.3" r=".63"/>
<circle cx="66" cy="168.5" r=".63"/>
<circle cx="78.1" cy="162.2" r=".63"/>
<circle cx="66" cy="185" r=".63"/>
<circle cx="78.1" cy="183.8" r=".63"/>
</g>
<g fill="none" stroke="#008400" stroke-width=".18">
<path d="M179.1 37.7h-7.7v6.4M186.7 37.7h6.3v8.9M33 49.1h2.6v5.1h-2.6M35.6 51.7h5M40.6 56.8h-3.8v3.8M43.8 45.3h-5.7v6.4M51.4 45.3h7v8.9h-2.5M79.4 58h-3.8v13.4M89.5 58h3.2v16.5M127 54.2h-29.8v20.3h-10.8M134.6 44.1h-27.9v36.8h5.1M134.6 59.3h10.2"/>
<path d="M134.6 42.8v6.3M139.7 59.3v6.4M152.4 54.2h8.9v3.8M175.3 49.1h-3.9v3.9M175.3 44.1h-30.5v5M190.5 46.6h6.3M248.3 54.9h-3.2v3.8M30.5 75.8v1.3M30.5 76.4h1.2M54 69.5h8.9M54 61.8h8.9M58.4 69.5v3.1"/>
<path d="M58.4 71.4h20.3M75.6 61.8h5M78.7 77.7v3.8M86.4 71.4v6.3M88.3 61.8h4.4M106.7 73.9h10.1M124.5 73.9h7.6v29.2h-21v3.2h-1.2M139.7 73.3v10.1h-12.7M238.8 61.2v-2.5h12.7v2.5M238.8 76.4v2.6h12.7v-2.6M25.4 84.7h-1.9v2.5M25.4 82.2v5"/>
<path d="M30.5 92.3v1.3M30.5 93h1.2M74.9 85.3v1.9M90.2 85.3h7v17.8h3.8v3.2h1.2M111.8 86h-5.1v5.1M238.8 91.1v-2.6h12.7v2.6M248.3 84.7h-3.2v3.8M251.5 96.1h8.2M259.1 93.6h11.4M259.1 98.7h11.4M267.3 96.1h3.2M238.8 103.8v2.5h12.7v-2.5"/>
<path d="M251.5 101.2h8.2M261.6 116.5h5.7M267.3 101.2h3.2M26 124.1h92.7M118.7 129.2h-13.9v20.9h3.8M123.2 138.7h-5.7v6.3M130.8 138.7h5.7v8.9M134 126.6h10.1M144.1 133.6h-71.1v36.8M164.5 121.5v7.7h10.1M170.8 132.3v17.2M175.3 137.4v12.1"/>
<path d="M185.4 132.3h-17.8v3.8M185.4 137.4h-17.8v1.3M189.9 121.5h1.9v7.7h-12.1M200.7 134.9v2.5M215.9 139.9v2.6M52.7 153.9h-6.3v6.4M60.3 153.9h6.4v8.9M104.8 145h3.8M116.2 145h2.5M116.2 150.1h2.5M117.5 150.1v3.8M134 147.6h10.1"/>
<path d="M167.6 143.8v3.8h17.8M167.6 141.2v1.3h17.8M170.8 157.1h41.3M179.7 142.5v7M184.1 147.6v1.9M200.7 142.5v2.5M201.9 151.4h-4.4v5.7M233.7 142.5v2.5h-2.6M241.3 142.5v13.3h-25.4v-8.2h-3.8v1.9M266.1 143.8h5M26 162.8h2.6M31.1 160.3h-2.5v5h2.5"/>
<path d="M38.7 160.3h10.2M38.7 165.3h10.2M41.3 160.3v6.3M58.4 170.4v2.6M64.1 162.8h8.9M69.8 176.8h2M73 175.5h-1.2v11.4h2.5M78.1 164.1v1.2M78.1 164.7h1.3M117.5 164.1v1.2M142.9 173h-54.6v17.7h-28M41.3 192v1.3"/>
<path d="M48.9 186.9v3.8h3.8M50.8 189.5v1.2M58.4 180.6v2.5M78.1 180.6v1.3M78.1 181.2h1.3M81.9 186.9h6.4"/>
</g>
<g fill="#008400" stroke="#008400" stroke-width=".25">
<circle cx="46.4" cy="160.3" r=".51"/>
<circle cx="28.6" cy="162.8" r=".51"/>
<circle cx="41.3" cy="160.3" r=".51"/>
<circle cx="46.4" cy="165.3" r=".51"/>
<circle cx="88.3" cy="186.9" r=".51"/>
<circle cx="66.7" cy="162.8" r=".51"/>
<circle cx="117.5" cy="145" r=".51"/>
<circle cx="104.8" cy="133.6" r=".51"/>
<circle cx="73" cy="162.8" r=".51"/>
<circle cx="104.8" cy="145" r=".51"/>
<circle cx="86.4" cy="74.5" r=".51"/>
<circle cx="58.4" cy="71.4" r=".51"/>
<circle cx="58.4" cy="69.5" r=".51"/>
<circle cx="58.4" cy="61.8" r=".51"/>
<circle cx="171.5" cy="44.1" r=".51"/>
<circle cx="193" cy="46.6" r=".51"/>
<circle cx="106.7" cy="73.9" r=".51"/>
<circle cx="132.1" cy="83.4" r=".51"/>
<circle cx="38.1" cy="51.7" r=".51"/>
<circle cx="35.6" cy="51.7" r=".51"/>
<circle cx="58.4" cy="54.2" r=".51"/>
<circle cx="88.3" cy="173" r=".51"/>
<circle cx="136.5" cy="147.6" r=".51"/>
<circle cx="215.9" cy="147.6" r=".51"/>
<circle cx="184.2" cy="157.1" r=".51"/>
<circle cx="179.7" cy="157.1" r=".51"/>
<circle cx="175.3" cy="157.1" r=".51"/>
<circle cx="184.2" cy="147.6" r=".51"/>
<circle cx="179.7" cy="142.5" r=".51"/>
<circle cx="175.3" cy="137.4" r=".51"/>
<circle cx="170.8" cy="132.3" r=".51"/>
<circle cx="197.5" cy="157.1" r=".51"/>
<circle cx="245.1" cy="106.3" r=".51"/>
<circle cx="245.1" cy="88.5" r=".51"/>
<circle cx="139.7" cy="59.3" r=".51"/>
<circle cx="134.6" cy="44.1" r=".51"/>
<circle cx="25.4" cy="84.7" r=".51"/>
<circle cx="75.6" cy="71.4" r=".51"/>
<circle cx="92.7" cy="74.5" r=".51"/>
<circle cx="101" cy="103.1" r=".51"/>
<circle cx="111.1" cy="103.1" r=".51"/>
<circle cx="75.6" cy="61.8" r=".51"/>
<circle cx="92.7" cy="61.8" r=".51"/>
<circle cx="165.1" cy="44.1" r=".51"/>
<circle cx="162.6" cy="44.1" r=".51"/>
<circle cx="245.1" cy="58.7" r=".51"/>
<circle cx="245.1" cy="79" r=".51"/>
<circle cx="78.1" cy="181.2" r=".51"/>
<circle cx="78.1" cy="164.7" r=".51"/>
<circle cx="30.5" cy="93" r=".51"/>
<circle cx="30.5" cy="76.4" r=".51"/>
<circle cx="164.5" cy="121.5" r=".51"/>
<circle cx="189.9" cy="121.5" r=".51"/>
<circle cx="117.5" cy="150.1" r=".51"/>
<circle cx="50.8" cy="190.7" r=".51"/>
<circle cx="71.8" cy="176.8" r=".51"/>
</g>
<g fill="none" stroke="#840000" stroke-width=".25">
<path d="M21.8 23.7h2.1v5.1h-2.1zM27.3 25.2h6.8v2.2h-6.8l-.6-1.1zM133.6 36.4h2v5.1h-2zM161.3 30.1h5.1v2.5h-5.1zM161.5 37.7h2.1v5.1h-2.1zM164.1 37.7h2v5.1h-2zM180.3 36.7h5.1v2h-5.1zM15.4 48h9.4l.6 1.1-.6 1.2h-9.4zM18 53.1h6.8l.6 1.1-.6 1.1h-6.8zM26.7 48.1h5v2.1h-5zM26.7 53.2h5v2h-5zM43.2 49.1l10.1 5.1-10.1 5.1z"/>
<path d="M45.1 44.3h5.1v2h-5.1zM57.4 55.5h2v5.1h-2zM124.6 50.5h2.2v3.1l-1.1 .6-1.1-.6zM135.3 46.8h3v2.2h-3l-.7-1.1zM138.6 56.9h2.2v1.8l-1.1 .6-1.1-.6zM141.1 46.8h3l.7 1.1-.7 1.1h-3zM152.6 50.5h2.2v3.1l-1.1 .6-1.1-.6zM177.8 41.5l10.2 5.1-10.2 5.1zM197.5 45.5h7v2.2h-7l-.7-1.1zM242.6 59.9h5v17.8h-5zM27.9 79.6l10.2 5.1-10.2 5.1zM53 63.1h2v5.1h-2z"/>
<path d="M57.4 73.9h2v5.1h-2zM61.8 63.1h2.1v5.1h-2.1zM80 76.7h5.1v2h-5.1zM80 70.4h5.1v2h-5.1zM114.3 78.4l10.2 5-10.2 5.1zM138.7 66.9h2v5.1h-2zM224.5 70.3h13.6l.7 1.1-.7 1.1h-13.6zM226.5 72.8h11.6l.7 1.1-.7 1.1h-11.6zM226.6 65.2h11.5l.7 1.1-.7 1.1h-11.5zM226.6 67.7h11.5l.7 1.1-.7 1.1h-11.5zM228.8 62.6h9.3l.7 1.1-.7 1.2h-9.3zM252.1 62.6h16.9v2.3h-16.9l-.6-1.2z"/>
<path d="M252.1 65.2h16.9v2.2h-16.9l-.6-1.1zM252.1 67.7h16.9v2.2h-16.9l-.6-1.1zM252.1 70.3h19v2.2h-19l-.6-1.1zM252.1 72.8h6.8v2.2h-6.8l-.6-1.1zM76.2 84.3h5.1v2.1h-5.1zM229.1 97.6h9l.7 1.1-.7 1.1h-9zM230.2 95h7.9l.7 1.1-.7 1.2h-7.9zM232.5 92.5h5.6l.7 1.1-.7 1.1h-5.6zM242.6 89.8h5v15.2h-5zM271.1 92.5h5.7v2.2h-5.7l-.6-1.1zM271.1 95h7.9v2.3h-7.9l-.6-1.2zM271.1 97.6h9v2.2h-9l-.6-1.1z"/>
<path d="M169.5 116.5h15.3v10.1h-15.3zM227.7 100.1h10.4l.7 1.1-.7 1.1h-10.4zM271.1 112.6h2.6v7.7h-2.6zM271.1 100.1h10.4v2.2h-10.4l-.6-1.1zM18.6 123h6.8l.6 1.1-.6 1.1h-6.8zM121.3 121.5l10.1 5.1-10.1 5.1zM124.5 137.7h5v2h-5zM144.8 132.5h7.9v2.2h-7.9l-.7-1.1zM144.8 125.5h5.6v2.2h-5.6l-.7-1.1zM188.6 131.1a6.6 6.6 0 0 1 0 7.6M189.2 138.7h3.2M189.2 131.1h3.2"/>
<path d="M189.3 131.1a6.6 6.6 0 0 1 0 7.6M192.4 131a5.2 5.2 0 0 1 4.4 3.8M196.8 134.9a5.2 5.2 0 0 1-4.4 3.8M203.9 136.2a6.6 6.6 0 0 1 0 7.5M207.6 136.1a5.2 5.2 0 0 1 4.5 3.8M207.6 136.1l-3.1 .1a6.6 6.6 0 0 1 0 7.5l3.1 .1M212.1 140a5.2 5.2 0 0 1-4.5 3.8M254.7 137.6h3.1l.6 1.1-.6 1.1h-3.1zM264.9 129.9h2.3v3.1l-1.1 .6-1.2-.6zM270 129.9h2.3v3.1l-1.2 .6-1.1-.6zM279.4 137.6h3.1v2.2h-3.1l-.6-1.1zM32.4 159.3h5.1v2h-5.1z"/>
<path d="M51.4 157.7l10.2 5.1-10.2 5.1zM94.1 157.9h7.5l.6 1.1-.6 1.1h-7.5zM103.5 158h5.1v2h-5.1zM109.9 149.1h5v2h-5zM109.9 144h5v2h-5zM121.3 142.5l10.1 5.1-10.1 5zM144.8 146.5h9v2.2h-9l-.7-1.1zM169.8 150.7h2v5.1h-2zM174.2 150.7h2.1v5.1h-2.1zM178.7 150.7h2v5.1h-2zM183.1 150.7h2.1v5.1h-2.1zM188.6 141.2a6.6 6.6 0 0 1 0 7.6"/>
<path d="M189.2 148.8h3.2M189.2 141.2h3.2M189.3 141.2a6.6 6.6 0 0 1 0 7.6M192.4 141.2a5.2 5.2 0 0 1 4.4 3.8M196.8 145.1a5.2 5.2 0 0 1-4.4 3.8M211.1 150.7h2v5.1h-2zM219.1 141.2a6.6 6.6 0 0 1 0 7.6M222.9 141.2a5.2 5.2 0 0 1 4.4 3.8M222.9 141.2h-3.2a6.6 6.6 0 0 1 0 7.6h3.2M227.3 145.1a5.2 5.2 0 0 1-4.4 3.8M235.1 143.1l1.1-.6 1.1 .6v7.6h-2.2zM237.6 143.1l1.2-.6 1.1 .6v11.7h-2.3z"/>
<path d="M258.5 152.8h3.1l.7 1.1-.7 1.1h-3.1zM258.5 155.3h3.1l.7 1.2-.7 1.1h-3.1zM259.9 150.3h1.7l.7 1.1-.7 1.1h-1.7zM266.1 150.1h5v7.6h-5zM267.5 144.4l1.1-.6 1.1 .6v1.7h-2.2zM275.6 155.3h1.7v2.3h-1.7l-.6-1.1zM275.6 150.3h3.1v2.2h-3.1l-.6-1.1zM275.6 152.8h3.1v2.2h-3.1l-.6-1.1zM18.3 161.7h7.1l.6 1.1-.6 1.1h-7.1zM32.4 164.3h5.1v2.1h-5.1zM40.3 167.9h2v5.1h-2zM40.3 175.5h2v5.1h-2z"/>
<path d="M45.3 166.6h2.1v5.1h-2.1zM49.7 177.2h2.2v11.6l-1.1 .7-1.1-.7zM57.4 174.2h2v5.1h-2zM59.7 169.4h5.1v2h-5.1zM63.5 175.8h5.1v2h-5.1zM75.6 167.9l10.1 5.1-10.1 5zM143.5 171.9h10.4v2.2h-10.4l-.6-1.1zM43.1 184.7v1M43.1 186.4v1M43.1 188.2v1M43.6 185v3.8M54 189.7h5.1v2.1h-5.1z"/>
<path d="M59.7 182.1h5.1v2h-5.1zM75.6 185.9h5v2.1h-5z"/>
<circle cx="133.3" cy="54.2" r="2.82"/>
<circle cx="146" cy="54.2" r="2.82"/>
<circle cx="264.8" cy="138.7" r="2.82"/>
<circle cx="272.4" cy="138.7" r="2.82"/>
<circle cx="116.2" cy="159" r="2.82"/>
<circle cx="42.2" cy="186.9" r="2.82"/>
</g>
<g fill="none" stroke="#0000c2" stroke-width=".18">
<path d="M124.6 19.1a.64 .64 0 0 1 .8 .7 .64 .64 0 0 1-.8 .6zM125.9 19.8h.6l.1-.2v-.3l-.2-.2h-.5v1.3M126.2 19.8l.4 .6M127.2 19.8h.4M127.8 19.1h-.6v1.3h.6M128.2 17.5h.5M128.3 19.8h.5M128.4 17.1v1.1l.3 .2M128.9 19.1h-.6v1.3M129.1 17.6l.2-.1 .3 .1 .1 .8M129.1 17.1v1.3M130.3 17.5v.9"/>
<path d="M130.6 17.5l-.2 .1-.1 .1M131.1 17.6l.3-.1 .2 .1-.1 .7-.3 .1-.2-.3zM132.2 17.5l.1 .8 .3 .1 .1-.2M132.7 17.5v.9M133.9 17.5v1l-.2 .3-.4-.1M133.9 17.6l-.4-.1-.2 .2 .1 .6h.5M134.5 17.6l.2-.1 .3 .1 .1 .8M134.5 17.1v1.3M129.4 20.3v.1M132.6 25.8l.3-.1 .3 .3-.2 .5h-.4M132.6 25.7v1.3M132.9 21.8l.1-.2 .3 .1 .1 .8"/>
<path d="M132.9 21.2v1.3M133.7 25.7v.9M134 22l.6-.1-.1-.2-.4-.1-.1 .2v.6h.5M134.1 25.7h.5M134.3 25.3v1.1l.3 .2M135.6 25.8l-.4-.1-.2 .3 .1 .5h.5M136.1 21.7l.3-.1 .3 .3-.1 .5h-.5M136.1 21.6v1.3M136.1 25.9l.2-.2 .3 .1 .1 .8M136.1 25.3v1.3M137.2 21.2v.1M137.2 26.2l.6-.1v-.3l-.4-.1-.2 .2 .1 .6h.5"/>
<path d="M137.2 21.6v.9M137.6 21.6h.5M137.8 21.2v1.1l.3 .2M138.8 25.8l-.3-.1-.2 .2 .1 .2 .4 .1v.3h-.5M138.9 23.7h.4M139 23.3v1.1l.3 .1M139.1 21.7l-.4-.1-.2 .3 .1 .5h.5M139.4 26.5v.1M139.6 21.8l.2-.2 .3 .1 .1 .8M139.6 21.2v1.3M139.8 23.7h.3l.3 .2-.1 .6h-.5M139.8 23.7v1.3"/>
<path d="M140.8 22.3v.2M140.9 23.7l.1 .8h.3l.2-.1M141.5 23.7v.8M141.9 23.7h.5M142.1 23.3v1.1l.3 .1M143.8 23.8l.1-.1h.3l.1 .8M143.8 23.7v.8M144.9 24.1l.5-.1v-.3h-.4l-.1 .2v.6h.5M145.9 24.1l.6-.1v-.3h-.4l-.2 .2 .1 .6h.5M147.6 23.7h-.3l-.3 .2 .1 .6h.5M147.6 23.3v1.2M148.7 23.7h-.3l-.2 .2v.1l.5 .2v.3h-.5"/>
<path d="M178.7 26.8l.6-.1-.1-.3h-.3l-.2 .2 .1 .6h.4M179.9 26.4v.8M180.2 26.4l-.3 .2M180.6 26.8l.6-.1-.1-.3h-.3l-.2 .2v.6h.5M181.7 26h.4l.2 .1-.4 .6M181.9 27.1v.1M200.5 36.3l.6-.1-.1-.2-.4-.1-.1 .2v.6h.5M201.5 35.6l.5-.1 .1 .2-.3 .6M201.8 36.6v.1M24.6 46.8l.2-.1 .4 .1v.5l-.1 .2h-.3l-.2-.1zM26.3 46.8l-.3-.1-.3 .2 .2 .6h.4M26.7 46.7h.5"/>
<path d="M26.9 46.3v1.1l.3 .1M68.6 44.2h.3l.2 .2-.1 .6h-.3l-.2-.2zM69.3 58.5v.5M69.4 59.4l-.1 .3 .2 .3 .6-.1v-.5M70.2 58.5l-.2 .3h-1.1M70.2 44.2h-.4l-.2 .2 .1 .6h.5M70.6 44.2h.5M70.8 43.7v1.1l.3 .2M97.9 54.9v.5M97.9 56.9l.6-.1 .2 .3v.3l-.6 .1-.2-.3zM97.9 55.7v.4l.2 .2 .6-.1v-.5M98.7 54.9l-.1 .3h-1.1"/>
<path d="M261.3 45v1.1l.2 .2M261.9 45.8l.6-.1v-.2l-.4-.1-.2 .2 .1 .6h.5M263 45.4l.2 .9 .4-.9M264 45.8l.6-.1-.1-.2-.3-.1-.2 .2v.6h.5M265.1 45v1.1l.2 .2M266.2 45.5l-.3-.1-.2 .2 .1 .2 .4 .1v.3h-.5M266.8 45.1l.4-.1 .2 .2-.4 .6M267 46.1v.2M69 60.6a.8 .8 0 0 1 1.2 .2l-.1 .3a.7 .7 0 0 1-.7 .2 .7 .7 0 0 1-.5-.5zM172.9 70.1l.2-.1h.3v.8M173.1 65.9h-.4l-.3 .2 .2 .5h.5M173.1 65.4v1.3"/>
<path d="M173.3 74l.4-.3v1.2M173.3 74.9h.7M174.1 65.9h-.3l-.2 .1 .1 .2 .4 .1v.3h-.5M174.4 70h-.3l-.1 .1v.2l.4 .2v.3h-.4M174.8 74.2l-.3-.2 .1-.2 .2-.1 .4 .1v.3l-.6 .2-.1 .1v.3l.3 .2h.3l.1-.2v-.4l-.2-.1M175.1 70v.8M175.5 65.9h.4M175.7 65.4v1.1l.2 .2M175.8 74.2l.2-.1h.3v.8M175.8 74.1v.8M176.1 70h-.3l-.2 .1 .1 .2 .4 .2v.3h-.5M176.3 74.3l.2-.2h.3l.1 .8"/>
<path d="M176.4 65.9v.8M176.5 70h.5M176.7 69.5v1.1l.3 .2M176.7 65.9l-.3 .2M177.2 65.9v.7l.3 .1 .2-.1M177.3 73.7l.4 1.2 .4-1.2M177.5 70h.3l.2 .1-.1 .7h-.3l-.3-.2zM177.7 65.9v.8M178.3 66.3l.6-.1-.1-.3h-.4l-.1 .1v.6h.5M178.6 74.8v.1M178.6 70v.8M178.9 70l-.3 .2"/>
<path d="M179 72.1l-.3-.1-.3 .3 .2 .5h.4M179 71.6v1.3M179.2 69.4a1.47 1.47 0 0 1 0 1.9M179.4 66.6v.1M179.4 65.9v.1M179.7 78.6l.6-.1-.1-.2-.4-.1-.1 .2v.6h.5M179.7 72.1l.3-.1 .3 .3-.2 .5-.3 .1-.2-.3zM180.8 72v.8l.4 .1 .1-.2M180.8 78.3l.2-.1 .3 .1v.7M180.8 78.2v.8M181.3 72v.9M181.9 67.5l.4 1.3 .4-1.3"/>
<path d="M181.9 72.1l.4-.1 .2 .3-.1 .5h-.5M181.9 71.6v1.3M182.5 78.3l-.4-.1-.2 .2 .1 .6h.5M182.5 77.8v1.2M183 67.5h.7M183 78.6l.6-.1v-.2l-.4-.1-.2 .2 .1 .6h.5M183.1 71.6v1.1l.2 .2M183.3 67.5v1.3M183.7 72.4l.6-.1v-.2l-.4-.1-.2 .2 .1 .6h.5M184.1 68.1h1M184.1 68.4h1M184.2 78.3l.2-.1 .3 .1v.7"/>
<path d="M184.2 78.2v.8M185.1 78.2h.5M185.3 77.8v1.1l.3 .1M185.6 67.6l.5-.1 .3 .3-.1 .2-.7 .8h.8M186.1 78.9v.1M187.5 67.5l-.5 .1-.2 .4 .1 .6 .2 .2 .4-.1 .1-.2-.1-.5h-.4l-.3 .2M187.9 79.8v1.3M188.1 68l.2-.1 .3 .1 .1 .8M188.1 67.9v.9M188.7 68.1l.1-.2 .4 .1v.8M189.6 67.5l.4 1.3 .5-1.3M57.1 88v1.1l.2 .2"/>
<path d="M61.4 90.6l.3-.1 .2 .1-.1 .7-.3 .1-.2-.3zM62.5 90.6l.2-.1 .3 .1v.8M62.5 90.5v.9M78.9 94.4l.2-.2h.3l.1 .8M83.6 96.3l.3-.1 .2 .2v.6l-.3 .1-.3-.3zM84.7 96.4l.2-.2 .3 .1 .1 .8M84.7 96.2v.9M182.5 98.5l.2-.2a.47 .47 0 0 1 .6 .5l-.1 .6-.2 .2h-.4a1 1 0 0 1-.1-1.1zM182.5 82.7l.7-.1-.1-.2-.4-.1-.2 .2 .1 .6h.5M182.7 99.3l.6 .4M183.1 92.7l.4-.1 .2 .2-.1 .6h-.5M183.1 90.5h.5"/>
<path d="M183.3 90.1v1.1l.3 .2M183.7 98.3h.8l-.4 .5 .3 .2v.5l-.1 .1-.6-.1M183.9 91l.7-.1-.1-.3-.4-.1-.2 .2 .1 .6h.5M184 84.8l.6-.1v-.3h-.4l-.2 .2 .1 .6h.5M184.3 92.2v.1M184.3 92.6v.8M184.5 82.3h.5M184.7 81.9v1.1l.3 .2M184.7 92.6h.4M184.8 92.2v1.1l.3 .1M185.1 80.3h.5v.8M185.1 90.5v.9"/>
<path d="M185.4 82.4l.2-.1 .3 .1v.8M185.4 81.9v1.3M185.4 90.5l-.3 .3M185.5 88.9l.6-.1v-.3h-.4l-.2 .2 .1 .6h.5M185.6 84.4h-.3l-.2 .2v.1l.5 .2v.3h-.5M185.6 80.6h-.4l-.2 .2 .1 .2h.5M186.1 98.8h-.3l-.2 .2v.1l.5 .2v.3h-.5M186.2 80.4l.2-.1h.3l.1 .8M186.2 80.3v.8M186.3 90.6l-.3-.1-.2 .2 .1 .2 .4 .1v.3h-.5M186.5 82.7l.6-.1-.1-.2-.3-.1-.2 .2v.6h.5M186.5 92.7h.5l.1 .7"/>
<path d="M186.9 91.3v.1M187 84.4h.5M187.1 88.5h-.3l-.2 .2 .1 .1 .4 .2v.3h-.5M187.1 92.9l-.4 .1-.2 .1v.3h.6M187.1 83.9v1.1l.4 .2M187.5 92.6h.5M187.6 98.8h.4l.2 .2-.1 .6h-.5M187.6 82.3v.9M187.6 98.3v1.3M187.7 88.1v.1M187.7 92.2v1.1l.3 .1M187.7 88.5v.8"/>
<path d="M187.9 84.5l.2-.1h.3v.8M187.9 83.9v1.3M187.9 80.3h-.3l-.3 .2 .2 .5h.4M188 82.3l-.4 .2M188.1 96.8l.1-.1 .3 .1 .1 .8M188.1 96.3v1.3M188.3 90.1h.7M188.4 82.4l.2-.1 .3 .1 .1 .8M188.4 82.3v.9M188.7 90.1v1.3M188.7 88.5h-.3l-.2 .2 .1 .1 .4 .2v.3h-.5M188.8 98.8h.5v.8"/>
<path d="M189 82.5l.2-.2 .2 .1 .1 .8M189 84.4h.5l.1 .8M189.2 88.5h.4M189.3 88.1v1l.3 .2M189.3 99.1h-.4l-.2 .2 .1 .3h.5M189.4 92.7l.2-.1 .3 .1v.7M189.4 92.2v1.2M189.4 90.7l.2-.2 .3 .1 .1 .8M189.4 90.1v1.3M189.6 84.7h-.4l-.2 .2v.3h.6M189.9 80.3h-.3l-.2 .1 .1 .2 .4 .1v.3h-.5M190 84.4h.5"/>
<path d="M190 88.5h.5l.1 .8M190.1 82.4h.5l.1 .8M190.2 83.9v1.1l.3 .2M190.2 96.9h.6l.1-.2-.1-.3-.1-.1h-.5v1.3M190.3 98.8h-.3l-.1 .2v.1l.4 .2v.3h-.4M190.5 96.9l.4 .7M190.5 80.4l.2-.1 .4 .1v.5l-.1 .1-.3 .1-.2-.1zM190.5 92.2v.1M190.5 92.6v.8M190.6 88.8h-.4l-.2 .2v.3h.6M190.6 90.1v.1M190.6 90.5v.9"/>
<path d="M190.7 82.6l-.5 .1-.2 .1 .2 .4 .5-.1M190.9 85.1v.1M190.9 99.2l.6-.1-.1-.3h-.3l-.2 .2 .1 .6h.4M191.2 88.6l.2-.1h.3v.8M191.2 88.5v.8M191.3 81.9v1.1l.1 .2M191.3 94.7h.4l.2 .2-.1 .5h-.5M191.3 94.7v1.2M191.4 96.6l.3-.3v1.3M191.4 97.6h.7M191.6 90.6l-.3-.1-.2 .2 .1 .2 .4 .1v.3h-.5M191.7 92.6v1l-.3 .3-.3-.1"/>
<path d="M191.7 92.7l-.4-.1-.2 .2 .1 .6h.5M192 99.5v.1M192.3 92.7l.2-.1 .3 .1v.7M192.3 92.2v1.2M192.4 95.1l.6-.1v-.3h-.4l-.2 .1 .1 .6h.5M192.5 96.3h.9l-.6 1.3M192.9 88.5h-.4l-.2 .2 .1 .6h.5M193.4 88.9l.6-.1-.1-.3h-.4l-.1 .2v.6h.5M193.5 94.8l.3-.1h.2l.1 .8M193.5 94.7v.8M194.8 96.8h.5l.1 .8M195.1 94.7h-.3l-.2 .1 .1 .2 .4 .1v.3h-.5"/>
<path d="M195.4 97l-.5 .1-.1 .2v.2h.6M195.7 94.7h.5l.1 .8M196 96.8l.2-.1 .3 .1v.8M196 96.7v.9M196.3 95h-.4l-.2 .2v.2h.6M196.7 94.7h.5M196.9 94.2v1.1l.3 .2M197.6 95.1l.5-.1v-.3h-.4l-.1 .1v.6h.5M197.7 96.8l-.4-.1-.2 .2 .1 .6h.5M197.7 96.3v1.3M199.1 94.7h-.3l-.2 .1 .1 .2 .4 .1v.3h-.5M58.6 107.7h.5l.1 .8"/>
<path d="M58.6 109.8h.5l.1 .8M59.2 108h-.4l-.2 .2v.3h.6M59.2 110.1h-.4l-.2 .2v.2h.6M59.8 107.8l.2-.1h.3v.8M59.8 109.9l.2-.2 .3 .1v.8M59.8 107.7v.8M59.8 109.7v.9M61.5 107.7l-.1 1.1-.2 .2-.3-.1M61.5 107.7h-.4l-.2 .2 .1 .6h.5M61.5 109.7l-.1 1.2-.2 .1-.3-.1M61.5 109.8l-.4-.1-.2 .3 .1 .5h.5M62.1 107.3v1.1l.2 .1"/>
<path d="M62.1 109.3v1.1l.2 .2M62.7 108.1l.6-.1-.1-.3h-.3l-.2 .2v.6h.5M62.7 110.2l.6-.1-.1-.3-.3-.1-.2 .2v.6h.5M63 115.9h.5M63.2 115.5v1.1l.3 .2M64 116l.1-.1 .3 .1 .1 .8M64 115.5v1.3M64.7 105.7l-.4-.1-.2 .3 .1 .5h.5M64.7 105.6v1.3M65.2 107.7h-.3l-.2 .2 .1 .1 .4 .2v.3h-.5M65.2 109.8l-.3-.1-.2 .2 .1 .2 .4 .1v.3h-.5M65.3 105.6l.1 .8 .3 .1 .1-.2"/>
<path d="M65.8 107.8l.2-.1h.3l.1 .8M65.8 109.9l.2-.2 .3 .1 .1 .8M65.8 105.6v.9M65.8 107.3v1.2M65.8 109.3v1.3M66.1 113.9v.7l.3 .1 .2-.1M66.1 116h.4l.1 .8M66.4 106l.6-.1-.1-.2-.4-.1-.1 .2v.6h.5M66.5 111.9h.5v.7M66.6 116.2l-.4 .1-.2 .2 .1 .2h.5M66.6 113.9v.8M67 107.7h.5v.8"/>
<path d="M67 109.8h.5v.8M67 112.1l-.4 .1-.2 .1 .1 .3h.5M67.2 116l.2-.1 .3 .1 .1 .8M67.2 115.9v.9M67.5 105.8l.2-.2 .3 .1 .1 .8M67.5 108h-.4l-.2 .2 .1 .3h.5M67.5 110.1h-.4l-.2 .2 .1 .2h.5M67.5 105.6v.9M67.6 111.9l.2-.1 .3 .1 .1 .7M67.6 113.9h-.3l-.1 .1v.2l.4 .1v.3h-.4M67.6 111.8v.8M67.8 116.1l.1-.2 .3 .1 .1 .8"/>
<path d="M68.1 107.7h.4l.2 .2-.1 .6h-.5M68.1 109.8l.4-.1 .2 .3-.1 .5h-.5M68.1 107.7v1.3M68.1 109.7v1.3M68.2 112l.2-.2 .3 .1v.7M68.2 114.3l.6-.1-.1-.3h-.3l-.2 .1v.6h.5M68.9 116l.4-.1 .2 .2-.1 .6h-.5M68.9 115.9v1.3M69.2 105.7l-.3-.1-.3 .3 .1 .5h.5M69.2 108.1l.6-.1v-.3h-.4l-.2 .2 .1 .6h.5M69.2 110.2l.6-.1v-.3l-.4-.1-.2 .2 .1 .6h.5M69.3 111.9l.4-.1 .3 .2-.2 .6h-.5"/>
<path d="M69.3 111.8v1.3M69.6 105.6l.4 .9M70.1 115.5v1.1l.2 .2M70.3 105.6l-.5 1.2-.2 .1M70.5 111.4v1.1l.2 .1M70.7 115.5v.1M70.7 115.9v.9M70.8 113.9h-.3l-.2 .2 .1 .5h.4M70.8 113.4v1.3M71.1 111.4v.1M71.1 111.8v.8M71.1 115.9h.5"/>
<path d="M71.3 115.5v1.1l.3 .2M71.5 113.4v.2M71.5 113.9v.8M71.6 111.8h.5M71.7 105.6v.9M71.8 111.4v1.1l.3 .1M72.1 105.6l-.4 .3M72.1 115.9v.8l.3 .1 .2-.2M72.5 105.7h.5v.8M72.5 111.8v.8h.3l.2-.1M72.5 113.9h-.3l-.2 .1 .1 .2 .4 .1v.3h-.5M72.6 115.9v.9"/>
<path d="M72.9 113.9h.5M73 105.9l-.4 .1-.2 .2 .2 .3 .4-.1M73 111.8v.8M73.1 113.4v1.1l.3 .2M73.6 105.8l.2-.2 .3 .1 .1 .8M73.6 105.6v.9M73.8 116l-.4-.1-.2 .2 .1 .6h.5M73.8 115.5v1.3M73.9 113.9h.3l.2 .2-.1 .5-.3 .1-.2-.1zM74.2 111.9l-.4-.1-.2 .2 .1 .6h.5M74.2 111.4v1.2M74.3 116.3l.6-.1v-.2l-.4-.1-.2 .2v.6h.6"/>
<path d="M74.7 112.2l.6-.1v-.2l-.4-.1-.2 .2 .1 .6h.5M75 113.9v.8M75.3 105.6v1l-.2 .3-.3-.1M75.3 105.7l-.3-.1-.3 .3 .2 .5h.4M75.3 113.9l-.3 .2M75.6 113.9h.4M75.7 113.4v1.1l.3 .2M75.9 106l.6-.1-.1-.2-.4-.1-.1 .2v.6h.5M76.5 113.4v.2M76.5 113.9v.8M76.8 111.9h.5l.1 .7M77.1 113.9h.3l.2 .1v.6l-.3 .1-.3-.2z"/>
<path d="M77.4 112.1l-.4 .1-.2 .1v.3h.6M78 111.9l.2-.1 .3 .1v.7M78 111.8v.8M78.2 114l.2-.1h.3l.1 .8M78.2 113.9v.8M79.7 111.9l-.4-.1-.2 .2 .1 .6h.5M79.7 111.4v1.2M218.5 117.8l.1-.1 .4 .1 .1 .5-.2 .2h-.3l-.1-.1zM219.6 117.8l.2-.1h.3l.1 .8M219.6 117.7v.8M221.2 117.7h-.3l-.2 .2 .1 .2 .4 .1v.3h-.5M221.8 118.4v.1"/>
<path d="M221.8 117.7v.2M233.2 119.8v.8M233.5 119.8l-.3 .2M234 119.3v.2M234 119.8v.8M234.6 119.9l.1-.1h.4v.8M234.6 119.8v.8M236.2 119.8v1.1l-.2 .1-.3-.1M236.2 119.8h-.3l-.2 .2 .1 .5h.4M236.9 119.9l.1-.1h.3l.1 .8M236.9 119.8v.8M237.4 119.9l.2-.1h.3v.8"/>
<path d="M238.6 119.8h.3l.3 .2-.2 .5-.3 .1-.2-.2zM240.2 119.8h-.3l-.3 .2 .2 .5h.4M240.2 119.3v1.3M100.7 139.5h.3l.3 .2-.2 .6h-.4M101.8 139.9l.6-.1-.1-.3h-.4l-.1 .1v.7h.5M224.8 128.1l.2-.1h.3l.1 .8M226.4 128h-.3l-.2 .2 .1 .1 .4 .2v.3h-.5M226.8 128h.5M226.9 121.8v.9M227 127.6v1l.3 .2M227.5 121.9l.2-.1 .3 .1 .1 .8M227.5 121.8v.9"/>
<path d="M227.7 128h.5l.1 .8M228.3 128.3h-.5l-.1 .2 .1 .3h.5M228.9 127.6v1l.2 .2M229.2 121.8v1.2l-.2 .1-.3-.1M229.2 121.9l-.3-.1-.3 .2 .2 .6h.4M229.5 127.6v1l.2 .2M229.8 121.9l.2-.1 .3 .1 .1 .8M229.8 121.8v.9M230 124l.2-.1h.3l.1 .8M230.1 128.4l.7-.1-.1-.3h-.4l-.2 .2 .1 .6h.5M230.4 122l.2-.2 .3 .1v.8M231.5 126l.3-.1 .2 .3-.1 .5-.3 .1-.3-.3z"/>
<path d="M231.6 121.9l.3-.1 .2 .1-.1 .7-.3 .1-.2-.3zM231.9 128h-.4l-.3 .2 .1 .6h.6M231.9 127.6v1.2M232.1 123.9v.8M232.4 128.7v.1M232.5 123.9l-.4 .2M232.9 123.4v.2M232.9 123.9v.8M233 126l-.3-.1-.2 .2 .1 .2 .4 .1v.3h-.5M233.2 121.9l-.3-.1-.3 .2 .1 .6h.5M233.2 121.4v1.3M233.5 124l.2-.1h.3l.1 .8"/>
<path d="M233.5 126.3l.6-.1v-.2l-.4-.1-.2 .2 .1 .6h.5M233.5 123.9v.8M235.2 123.9v1l-.2 .2h-.3M235.2 123.9h-.3l-.3 .2 .1 .6h.5M235.5 125.9h.4M235.7 125.5v1.1l.2 .2M235.8 124l.2-.1h.3l.1 .8M235.8 123.9v.8M236.4 124l.2-.1h.3v.8M236.4 126.1l.2-.2 .3 .1v.8M236.4 125.5v1.3M237.5 125.5v.1"/>
<path d="M237.5 125.9v.9M237.6 123.9h.3l.2 .2v.4l-.2 .2h-.3l-.1-.2zM238.6 126l-.3-.1-.2 .2v.2l.5 .1v.3h-.5M239.2 123.9h-.3l-.3 .2 .1 .6h.5M239.2 123.4v1.3M239.7 123.3a1.47 1.47 0 0 1 0 1.9M98 151.9l.2-.1 .3 .1 .1 .7M98.6 152l.1-.2 .3 .1 .1 .7M99.5 145.6h.5M99.6 152.2l.7-.1-.1-.2-.4-.1-.2 .2 .1 .6h.5M99.7 145.2v1.1l.3 .2M100.4 145.2v.1"/>
<path d="M100.4 145.6v.9M100.5 148.1l.6-.1-.1-.3h-.3l-.2 .2v.6h.5M101.4 143.6h.5M101.6 145.7l-.4-.1-.2 .3 .1 .5h.5M101.6 143.1v1.1l.3 .2M101.6 154.3l.6-.1v-.3h-.4l-.2 .1 .1 .7h.5M102.1 141.6h.5l.1 .8M102.4 143.6h.3l.3 .2-.2 .6h-.3l-.1-.1zM102.6 147.7h.5v.8M102.7 141.8l-.5 .1-.1 .2v.2h.6M102.8 154.2h1M103.1 148l-.4 .1-.2 .1 .1 .3h.5"/>
<path d="M103.5 149.8h-.4l-.3 .2 .2 .5h.5M103.6 155.9v1l-.3 .3-.3-.1M103.6 156l-.4-.1-.2 .3 .1 .5h.5M103.9 150.2l.6-.1v-.3h-.4l-.2 .1 .1 .6h.5M104.2 156.1l.1-.2 .3 .1 .1 .8M104.2 155.5v1.3M105.3 156.6v.2M204.2 159.8v1.3M206 159.8v1.1l.2 .2M207.8 159.8v1.1l.3 .2M208.5 159.8v.1M107.5 168.8v.2"/>
<path d="M107.5 169.3v.8M108.1 169.4l.2-.1 .4 .1v.5l-.1 .1-.3 .1-.2-.1zM109.3 169.4l.2-.1h.3v.8M109.3 169.3v.8M117 176.8l-.5 1.1-.1 .1M117.4 176.3v.2M117.4 176.8v.8M118.1 176.9l.1-.1h.3l.1 .8M118.1 176.8v.8M119.7 176.8v1.1l-.2 .1h-.3M119.7 176.8h-.3l-.2 .2 .1 .6h.4M120.8 178.4v.1"/>
<path d="M121.3 176.8h.5l.1 .8M121.4 178.8l.1 .8 .3 .1 .2-.2M121.9 177.1h-.5l-.1 .2v.3h.6M122 178.8v.9M122.5 176.9l.2-.1h.3v.8M122.5 176.8v.8M123 178.9l-.3-.1-.2 .2 .1 .2 .4 .1v.3h-.5M123.4 178.8h.5M123.6 178.4v1.1l.3 .2M124.3 178.9h.5l.1 .8M124.9 179.1l-.4 .1-.2 .2v.2h.6M125.5 178.9l.4-.1 .2 .3-.1 .5h-.5"/>
<path d="M125.5 178.4v1.3M126.6 178.4v1.1l.2 .2M127.3 179.2l.5-.1v-.2l-.4-.1-.1 .2v.6h.5M152.1 170.6l-.3-.1-.2 .2v.2l.5 .1v.3h-.5M152.6 170.9l.6-.1v-.2l-.4-.1-.2 .2 .1 .6h.5M201.4 160.4l.2-.2 .3 .1v.8M202.6 160.3l.3-.1 .2 .2-.1 .6-.3 .1-.2-.2zM204.2 160.3l-.3-.1-.3 .2 .2 .6h.4M204.8 160.2l.1 .8 .3 .1 .2-.2M205.4 160.2v.9M206.7 160.3h.4l.1 .8M207.2 160.5l-.4 .1-.2 .2 .1 .2h.5"/>
<path d="M207.6 160.2h.5M208.5 160.2v.9M209.1 160.3l.2-.1 .3 .1 .1 .1-.1 .6-.3 .1-.2-.2zM209.8 162.3h.5M210 161.8v1.1l.3 .2M210.3 160.3l.2-.1 .3 .1v.8M210.3 160.2v.9M210.6 162.7l.7-.1-.1-.3h-.4l-.2 .2 .1 .6h.5M212.3 162.3h-.3l-.3 .2 .2 .6h.4M212.3 161.8v1.3M213.7 162.3h.5M213.9 161.8v1.1l.3 .2"/>
<path d="M214.6 162.3v.8M215 162.3l-.4 .2M215.4 161.8v.2M215.4 162.3v.8M216 162.3h.5l.1 .8M216.6 162.6h-.4l-.2 .2v.3h.6M217.2 162.4l.1-.1h.4v.8M217.2 162.3v.8M218.9 162.3v1l-.3 .2h-.3M218.9 162.3h-.4l-.2 .2 .1 .6h.5M219.5 161.8v1.1l.2 .2M220.1 162.7l.6-.1-.1-.3h-.3l-.2 .2v.6h.5"/>
<path d="M221.1 161.7a1.47 1.47 0 0 1 0 1.9M270.4 163l.3-.1 .3 .2-.2 .6h-.4M270.4 162.9v1.3M271.5 163h.5l.1 .7M272.1 163.2l-.5 .1-.2 .1 .1 .3h.6M272.4 160.9h.4M272.5 160.4v1.1l.3 .2M272.7 162.5v.1M272.7 162.9v.8M273.3 161l.2-.1h.3l.1 .2-.1 .5-.3 .1-.2-.1zM273.3 162.9v.8M273.6 162.9l-.3 .2"/>
<path d="M274.4 160.9v.8M274.8 160.9h-.3l-.1 .2M275.6 160.9h-.3l-.2 .1 .1 .2 .4 .1v.3h-.5M25.3 196.3l.6-.1-.1-.2-.3-.1-.2 .2v.6h.5M55.5 195.5v1.1l.2 .2M56.2 196.3l.6-.1-.1-.2-.4-.1-.1 .2v.6h.5M57.2 195.9l.3 .9 .3-.9M58.2 196.3l.6-.1v-.2l-.4-.1-.2 .2 .1 .6h.5M59.4 195.5v1.1l.1 .2M110 196.1v-1.2l.4 .9 .4-.9v1.2M110.6 189.4l.6-.2v-.4l-.2-.1h-.4v1.3M110.8 189.4l.5 .6"/>
<path d="M111.3 194.9h.8l-.4 .4 .4 .2-.1 .6h-.5l-.2-.1M111.8 189.3h.4M112.4 188.7h-.6v1.3h.6M112.6 195l.5-.1 .2 .3v.2l-.8 .7h.8M113 189.3h.4M113.6 188.7h-.6v1.3M114.1 189.8v.2M114.1 194.8l-.3 .9h.8M114.4 195.3v.8M115.1 196v.1M116.8 185l.2 .8 .3-.6 .2 .6 .3-.8M117.3 183.1l.2-.1h.3l.1 .8"/>
<path d="M118.2 185.1h.5l.1 .7M118.8 185.3l-.4 .1-.2 .1v.3h.6M118.9 191.2h.6M119 183h-.3l-.3 .2 .1 .5h.5M119 182.5v1.3M119.4 185.1l.2-.1 .3 .1v.7M119.4 185v.8M119.5 190.7l-.3 .2v1.1M119.9 191.5h.9M120.3 185h.5M120.5 184.6v1.1l.3 .1M120.6 182.5v1.1l.2 .2"/>
<path d="M120.6 193.3h.5v.8M121.1 187.1h-.3l-.3 .2 .1 .6h.5M121.1 193.5l-.4 .1-.2 .2 .1 .2h.5M121.2 183.4l.6-.1-.1-.3h-.3l-.2 .1 .1 .6h.4M121.3 181.1h.6l.1-.2-.1-.3-.2-.1h-.4v1.2M121.3 185.7v.1M121.6 181.1l.4 .6M121.6 193.2l.3 .9 .2-.6 .3 .6 .2-.9M121.7 187.1h.3l.2 .1v.7h-.3l-.3-.2zM122 191.2h-.4l-.2 .2 .1 .6h.5M122.4 183h.4l.1 .8M122.5 180.5h.4l.2 .1-.4 .6"/>
<path d="M122.5 191.6l.6-.1-.1-.3h-.3l-.2 .2v.6h.5M122.7 181.6v.1M122.8 187.2l.2-.1h.3l.1 .8M122.8 187.1v.8M122.9 183.3h-.4l-.2 .2 .1 .2h.5M122.9 193.2h.5M123.1 192.8v1.1l.3 .2M123.4 183l.3 .8 .3-.8M123.6 191.3l.2-.1h.3l.1 .8M123.6 181.2h1M123.6 191.2v.8M123.9 193.3l.3-.1 .2 .3-.1 .5-.3 .1-.2-.2z"/>
<path d="M124 187.2l.2-.1h.3v.8M124 187.1v.8M124.1 180.8v.9M124.4 183.4l.6-.1-.1-.3h-.3l-.2 .1 .1 .6h.4M124.6 191.2h.5M124.8 190.7v1.1l.3 .2M125 193.3l.3-.1 .2 .2 .1 .4-.2 .2-.3 .1-.2-.2v-.4zM125.1 187.5l.6-.1-.1-.3h-.4l-.1 .1v.7h.5M125.2 181.1h.6l.1-.5-.2-.1h-.5v1.2M125.4 191.6l.6-.1v-.3h-.4l-.2 .2 .1 .6h.5M125.5 181.1l.4 .6M125.9 193.2h.5"/>
<path d="M126.1 192.8v1.1l.3 .2M126.4 180.5h.4l.2 .1-.4 .6M126.6 191.2v.8M126.6 181.6v.1M126.8 187.1h-.4l-.2 .2 .1 .6h.5M126.8 193.4l.2-.2 .3 .1 .1 .8M126.8 192.8v1.3M126.9 191.2l-.3 .2M127.1 187.1h.5M127.3 186.6v1.1l.3 .2M128 194l-.1 .3M129.4 209.3h1"/>
<path d="M130.8 208.5l.4 1.3 .4-1.3M131.9 207h.5l.1 .7M132.5 207.2l-.4 .1-.2 .1v.3h.6M132.6 209h-.4l-.2 .2 .1 .5h.5M133.1 207l.2-.1 .3 .1v.7M133.1 206.9v.8M133.7 209h-.4l-.2 .2 .1 .5h.5M134 204.8h.5M134.2 204.4v1.1l.3 .2M134.8 207l-.4-.1-.2 .2 .1 .6h.5M134.8 206.5v1.2M134.9 204.9l.4-.1 .2 .3-.1 .5h-.5"/>
<path d="M134.9 204.8v1.3M135.2 209h.5v.8M135.7 209.3h-.4l-.2 .2 .1 .2h.5M135.9 202.8l.3 .8 .2-.6 .3 .6 .2-.8M136 204.8l.1 .8 .3 .1 .2-.1M136.2 206.5l.4 1.2 .4-1.2M136.3 209.1l.2-.1h.3l.1 .8M136.3 209v.8M136.6 204.8v.9M137 204.8h.5M137.2 204.4v1.1l.3 .2M137.4 202.9l.2-.1h.3l.1 .2-.1 .6h-.3l-.2-.1z"/>
<path d="M137.4 207.3l.6-.1-.1-.2-.3-.1-.2 .2v.6h.5M138 209h-.3l-.3 .2 .2 .5h.4M138 208.5v1.3M138.5 207.3l.6-.1-.1-.2-.4-.1-.1 .2v.6h.5M138.5 202.8l.1 .8h.3l.2-.1M138.9 204.9l.3-.1 .3 .3-.1 .5-.3 .1-.2-.1zM139.1 202.8v.8M139.6 207.6v.1M139.7 202.4v1l.2 .2M139.9 204.8h.4M140.3 204.4l-.3 .2v1.1M140.9 202.8h-.4l-.2 .2 .1 .6h.5"/>
<path d="M140.9 202.4v1.2M141.6 204.8h.4M141.7 204.4v1.1l.3 .2M142.4 202.8h.4l.3 .2-.1 .6h-.6M142.4 205l.2-.2 .4 .1v.8M142.4 202.4v1.2M142.4 204.4v1.3M143.5 203.2l.6-.1v-.3h-.4l-.2 .2 .1 .6h.5M143.5 205.3l.6-.1v-.3l-.4-.1-.2 .2 .1 .6h.5"/>
</g>
<g fill="none" stroke="#0000c2" stroke-width=".18" stroke-dasharray=".4 .4">
<path d="M60.3 50.4h7.6M67.9 50.4v41.9M49.5 61.2v31.1M49.5 61.2l10.8-10.8M71.1 66.9h19.7M71.1 66.9v31.1M90.8 66.9v31.1M67.9 92.3h-18.4M71.1 98h19.7M161.3 115.2h81.3M242.6 115.2v49.5M89.5 120.3v50.8"/>
<path d="M154.3 120.3h-64.8M254 129.2v35.5M283.2 129.2h-29.2M17.1 148.8v48.9M87.6 148.8h-70.5M53.3 172.3v8.9M61 164.7l-7.7 7.6M69.8 164.7h-8.8M69.8 164.7v24.1M89.5 171.1h51.5M90.8 175.5h38.1M90.8 175.5v21.6"/>
<path d="M128.9 175.5v21.6M141 171.1v-2.6M141 168.5h13.3M154.3 168.5v-48.2M161.3 164.7v-49.5M242.6 164.7h-81.3M254 164.7h29.2M283.2 164.7v-35.5M17.1 197.7h70.5M61 188.8l-7.7-7.6M69.8 188.8h-8.8M69.8 188.8l5.1 5.1"/>
<path d="M74.9 193.9h15.9M87.6 197.7v-48.9M128.9 197.1h-38.1"/>
</g>
<g fill="#840000" stroke="#840000" stroke-width=".18">
<path d="M51.4 67.1l.3 .7h-.5l.2-.7v2.2z"/>
<path d="M52.2 67.1v2.2l-.3-.7h.6l-.3 .7z"/>
<path d="M162.6 143.6h.8v.3h-.8z"/>
<path d="M162.6 141.1h.8v.2h-.8z"/>
<path d="M162.6 138.6h.8v.2h-.8z"/>
<path d="M162.6 136h.8v.3h-.8z"/>
<path d="M241.2 137.4h.2v.9h-.2z"/>
<path d="M238.6 137.4h.3v.9h-.3z"/>
<path d="M236.1 137.4h.2v.9h-.2z"/>
<path d="M233.6 137.4h.2v.9h-.2z"/>
<path d="M133.3 56l.6-.5 .5 1z"/>
<path d="M145.5 55.5l.5 .5-1 .5z"/>
<path d="M264.8 140.5l.5-.6 .5 1.1z"/>
<path d="M271.9 139.9l.5 .6-1 .5z"/>
<path d="M105 105.6l.4-.3h.4v2a1.03 1.03 0 0 1-.9-.6 1.03 1.03 0 0 1 .1-1.1z"/>
<path d="M106.3 105.3a1.02 1.02 0 0 1 1 1 1.02 1.02 0 0 1-1 1z"/>
<path d="M83.4 61.2l.4-.3 .4-.1v2.1a1.03 1.03 0 0 1-.9-.6 1.03 1.03 0 0 1 .1-1.1z"/>
<path d="M84.7 60.8a1.02 1.02 0 0 1 1 1 1.02 1.02 0 0 1-1 1.1z"/>
<path d="M24 26.3l1.1-.5v1z"/>
<path d="M116.2 160.8l.5-.5 .5 1z"/>
<path d="M59.6 176.8l1.1-.5v1z"/>
<path d="M41.8 186.6l1 .3-1 .4z"/>
<circle cx="41.3" cy="188.7" r=".28"/>
<circle cx="41.3" cy="185.2" r=".28"/>
</g>
<g fill="none" stroke="#840000" stroke-width=".51">
<path d="M132.7 52.3v3.8M146.7 52.3v3.8M119.9 71.9v4M121.4 71.9v4M254.5 91.6v4M254.5 96.6v4.1M256 91.6v4M256 96.6v4.1M262.8 94.1v4.1M262.8 99.2v4M264.3 94.1v4.1M264.3 99.2v4"/>
<path d="M264.2 136.8v3.8M273 136.8v3.8M55.8 151.9v4.1M57.3 151.9v4.1M115.6 157.1v3.8"/>
</g>
<g fill="#ffffc2" stroke="#ffffc2" stroke-width=".18">
<path d="M271.1 112.6h2.6v7.7h-2.6z"/>
<path d="M43.2 49.1l10.1 5.1-10.1 5.1z"/>
<path d="M114.3 78.4l10.2 5-10.2 5.1z"/>
<path d="M177.8 41.5l10.2 5.1-10.2 5.1z"/>
<path d="M27.9 79.6l10.2 5.1-10.2 5.1z"/>
<path d="M51.4 157.7l10.2 5.1-10.2 5.1z"/>
<path d="M75.6 167.9l10.1 5.1-10.1 5z"/>
<path d="M121.3 121.5l10.1 5.1-10.1 5.1z"/>
<path d="M121.3 142.5l10.1 5.1-10.1 5z"/>
<path d="M192.4 131a5.2 5.2 0 0 1 4.4 3.8l-5 1.4z"/>
<path d="M191.8 133.5l5 1.4a5.2 5.2 0 0 1-4.4 3.8z"/>
<path d="M189.2 138.7h3.2z"/>
<path d="M189.2 131.1h3.2z"/>
<path d="M189.2 131.1h3.2v7.6h-3.2a6.7 6.7 0 0 0 0-7.6z"/>
<path d="M207.6 136.1a5.2 5.2 0 0 1 4.5 3.8l-5 1.4z"/>
<path d="M207.1 138.6l5 1.4a5.2 5.2 0 0 1-4.5 3.8z"/>
<path d="M204.5 143.8h3.1z"/>
<path d="M204.5 136.1h3.1z"/>
<path d="M204.5 136.1h3.1v7.7h-3.1a6.7 6.7 0 0 0 0-7.7z"/>
<path d="M222.9 141.2a5.2 5.2 0 0 1 4.4 3.8l-5 1.3z"/>
<path d="M222.3 143.7l5 1.4a5.2 5.2 0 0 1-4.4 3.8z"/>
<path d="M219.7 148.8h3.2z"/>
<path d="M219.7 141.2h3.2z"/>
<path d="M219.7 141.2h3.2v7.6h-3.2a6.7 6.7 0 0 0 0-7.6z"/>
<path d="M192.4 141.2a5.2 5.2 0 0 1 4.4 3.8l-5 1.3z"/>
<path d="M191.8 143.7l5 1.4a5.2 5.2 0 0 1-4.4 3.8z"/>
<path d="M189.2 148.8h3.2z"/>
<path d="M189.2 141.2h3.2z"/>
<path d="M189.2 141.2h3.2v7.6h-3.2a6.7 6.7 0 0 0 0-7.6z"/>
<path d="M169.5 116.5h15.3v10.1h-15.3z"/>
<path d="M242.6 89.8h5v15.2h-5z"/>
<path d="M266.1 150.1h5v7.6h-5z"/>
<path d="M161.3 30.1h5.1v2.5h-5.1z"/>
<path d="M242.6 59.9h5v17.8h-5z"/>
</g>
<g fill="none" stroke="#008484" stroke-width=".18">
<path d="M156.6 28v1.1l.1 .2M170.4 28.5h.3l.2 .1-.1 .7h-.3l-.2-.2zM172 28.5h-.3l-.3 .2 .2 .6h.4M172 28v1.3M43.7 51.8h1M91.5 55l.7-.1-.1-.2-.4-.1-.2 .2 .1 .6h.5M178.3 44.1h1M244.9 64.9h.8M245.7 64.4h-.8v.3l.1 .2M28.4 87.3h1M29.8 87.3l1.2 .5-1.2 .4M30.6 85.9v1"/>
<path d="M114.8 81h1M244.9 92.6v.5M245.7 92.6l-.2 .3h-1.1M112.9 101h-.3l-.3 .2 .1 .6h.5M113.3 101h.5M113.5 100.6v1l.3 .2M121.8 129.2h1M228.3 135.3v.8M228.7 135.3h-.3l-.1 .2M241.1 134.8v.2M241.1 135.3v.8M242.2 135.3v1.1l-.2 .1h-.3"/>
<path d="M242.2 135.3h-.3l-.3 .2 .1 .6h.5M283 121.3l.3 .8M283.6 121.3l-.4 1.1-.2 .2M121.8 145.1h1M257.6 158.9h.5l.1-.4-.6-.2v1.3h.5l.2-.2v-.2l-.3-.3M279.6 159.2l.6-.1-.1-.3h-.3l-.2 .1 .1 .7h.4M280.6 158.8h.5M280.7 158.3v1.1l.4 .2M51.9 160.3h1M76 170.5h1M77.4 175.6l1.3 .4-1.3 .4M78.2 174.2v1"/>
</g>
<path d="M85.1 84.1l2.5 1.2-2.5 1.3zM87.6 84.1v2.5" fill="none" stroke="#840000" stroke-width=".2"/>
<path d="M33.8 74.9v3.1M33.8 91.4v3.1M176.7 127.6v3.1M81.4 163.2v3M81.4 179.7v3" fill="none" stroke="#840000" stroke-width=".33"/>
<path d="M34.8 74.9v3.1M34.8 91.4v3.1M177.7 127.6v3.1M82.4 163.2v3M82.4 179.7v3" fill="none" stroke="#840000" stroke-width=".3"/>
<use href="#words"/>
</svg>
